VERSION 5.8 ;
BUSBITCHARS "[]" ;
DIVIDERCHAR "/" ;
UNITS
    DATABASE MICRONS 1000 ;
END UNITS

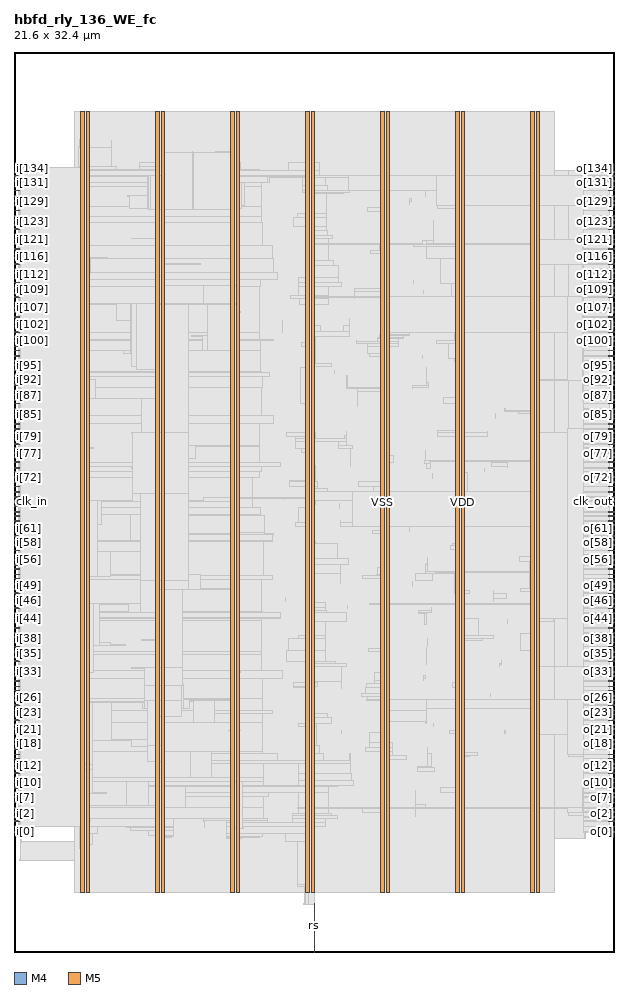
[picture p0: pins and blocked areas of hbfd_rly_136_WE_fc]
MACRO hbfd_rly_136_WE_fc
  FOREIGN hbfd_rly_136_WE_fc 0 0 ;
  CLASS BLOCK ;
  SIZE 21.6 BY 32.4 ;
  PIN clk_in
    DIRECTION INPUT ;
    USE SIGNAL ;
    PORT
      LAYER M4 ;
        RECT  0 16.224 0.192 16.248 ;
    END
  END clk_in
  PIN clk_out
    DIRECTION OUTPUT ;
    USE SIGNAL ;
    PORT
      LAYER M4 ;
        RECT  21.408 16.224 21.6 16.248 ;
    END
  END clk_out
  PIN i[0]
    DIRECTION INPUT ;
    USE SIGNAL ;
    PORT
      LAYER M4 ;
        RECT  0 4.32 0.192 4.344 ;
    END
  END i[0]
  PIN i[100]
    DIRECTION INPUT ;
    USE SIGNAL ;
    PORT
      LAYER M4 ;
        RECT  0 21.984 0.192 22.008 ;
    END
  END i[100]
  PIN i[101]
    DIRECTION INPUT ;
    USE SIGNAL ;
    PORT
      LAYER M4 ;
        RECT  0 22.128 0.192 22.152 ;
    END
  END i[101]
  PIN i[102]
    DIRECTION INPUT ;
    USE SIGNAL ;
    PORT
      LAYER M4 ;
        RECT  0 22.32 0.192 22.344 ;
    END
  END i[102]
  PIN i[103]
    DIRECTION INPUT ;
    USE SIGNAL ;
    PORT
      LAYER M4 ;
        RECT  0 22.512 0.192 22.536 ;
    END
  END i[103]
  PIN i[104]
    DIRECTION INPUT ;
    USE SIGNAL ;
    PORT
      LAYER M4 ;
        RECT  0 22.656 0.192 22.68 ;
    END
  END i[104]
  PIN i[105]
    DIRECTION INPUT ;
    USE SIGNAL ;
    PORT
      LAYER M4 ;
        RECT  0 22.848 0.192 22.872 ;
    END
  END i[105]
  PIN i[106]
    DIRECTION INPUT ;
    USE SIGNAL ;
    PORT
      LAYER M4 ;
        RECT  0 23.04 0.192 23.064 ;
    END
  END i[106]
  PIN i[107]
    DIRECTION INPUT ;
    USE SIGNAL ;
    PORT
      LAYER M4 ;
        RECT  0 23.184 0.192 23.208 ;
    END
  END i[107]
  PIN i[108]
    DIRECTION INPUT ;
    USE SIGNAL ;
    PORT
      LAYER M4 ;
        RECT  0 23.376 0.192 23.4 ;
    END
  END i[108]
  PIN i[109]
    DIRECTION INPUT ;
    USE SIGNAL ;
    PORT
      LAYER M4 ;
        RECT  0 23.568 0.192 23.592 ;
    END
  END i[109]
  PIN i[10]
    DIRECTION INPUT ;
    USE SIGNAL ;
    PORT
      LAYER M4 ;
        RECT  0 6.096 0.192 6.12 ;
    END
  END i[10]
  PIN i[110]
    DIRECTION INPUT ;
    USE SIGNAL ;
    PORT
      LAYER M4 ;
        RECT  0 23.712 0.192 23.736 ;
    END
  END i[110]
  PIN i[111]
    DIRECTION INPUT ;
    USE SIGNAL ;
    PORT
      LAYER M4 ;
        RECT  0 23.904 0.192 23.928 ;
    END
  END i[111]
  PIN i[112]
    DIRECTION INPUT ;
    USE SIGNAL ;
    PORT
      LAYER M4 ;
        RECT  0 24.096 0.192 24.12 ;
    END
  END i[112]
  PIN i[113]
    DIRECTION INPUT ;
    USE SIGNAL ;
    PORT
      LAYER M4 ;
        RECT  0 24.24 0.192 24.264 ;
    END
  END i[113]
  PIN i[114]
    DIRECTION INPUT ;
    USE SIGNAL ;
    PORT
      LAYER M4 ;
        RECT  0 24.432 0.192 24.456 ;
    END
  END i[114]
  PIN i[115]
    DIRECTION INPUT ;
    USE SIGNAL ;
    PORT
      LAYER M4 ;
        RECT  0 24.576 0.192 24.6 ;
    END
  END i[115]
  PIN i[116]
    DIRECTION INPUT ;
    USE SIGNAL ;
    PORT
      LAYER M4 ;
        RECT  0 24.768 0.192 24.792 ;
    END
  END i[116]
  PIN i[117]
    DIRECTION INPUT ;
    USE SIGNAL ;
    PORT
      LAYER M4 ;
        RECT  0 24.96 0.192 24.984 ;
    END
  END i[117]
  PIN i[118]
    DIRECTION INPUT ;
    USE SIGNAL ;
    PORT
      LAYER M4 ;
        RECT  0 25.104 0.192 25.128 ;
    END
  END i[118]
  PIN i[119]
    DIRECTION INPUT ;
    USE SIGNAL ;
    PORT
      LAYER M4 ;
        RECT  0 25.296 0.192 25.32 ;
    END
  END i[119]
  PIN i[11]
    DIRECTION INPUT ;
    USE SIGNAL ;
    PORT
      LAYER M4 ;
        RECT  0 6.24 0.192 6.264 ;
    END
  END i[11]
  PIN i[120]
    DIRECTION INPUT ;
    USE SIGNAL ;
    PORT
      LAYER M4 ;
        RECT  0 25.488 0.192 25.512 ;
    END
  END i[120]
  PIN i[121]
    DIRECTION INPUT ;
    USE SIGNAL ;
    PORT
      LAYER M4 ;
        RECT  0 25.632 0.192 25.656 ;
    END
  END i[121]
  PIN i[122]
    DIRECTION INPUT ;
    USE SIGNAL ;
    PORT
      LAYER M4 ;
        RECT  0 25.824 0.192 25.848 ;
    END
  END i[122]
  PIN i[123]
    DIRECTION INPUT ;
    USE SIGNAL ;
    PORT
      LAYER M4 ;
        RECT  0 26.016 0.192 26.04 ;
    END
  END i[123]
  PIN i[124]
    DIRECTION INPUT ;
    USE SIGNAL ;
    PORT
      LAYER M4 ;
        RECT  0 26.16 0.192 26.184 ;
    END
  END i[124]
  PIN i[125]
    DIRECTION INPUT ;
    USE SIGNAL ;
    PORT
      LAYER M4 ;
        RECT  0 26.352 0.192 26.376 ;
    END
  END i[125]
  PIN i[126]
    DIRECTION INPUT ;
    USE SIGNAL ;
    PORT
      LAYER M4 ;
        RECT  0 26.496 0.192 26.52 ;
    END
  END i[126]
  PIN i[127]
    DIRECTION INPUT ;
    USE SIGNAL ;
    PORT
      LAYER M4 ;
        RECT  0 26.688 0.192 26.712 ;
    END
  END i[127]
  PIN i[128]
    DIRECTION INPUT ;
    USE SIGNAL ;
    PORT
      LAYER M4 ;
        RECT  0 26.88 0.192 26.904 ;
    END
  END i[128]
  PIN i[129]
    DIRECTION INPUT ;
    USE SIGNAL ;
    PORT
      LAYER M4 ;
        RECT  0 27.024 0.192 27.048 ;
    END
  END i[129]
  PIN i[12]
    DIRECTION INPUT ;
    USE SIGNAL ;
    PORT
      LAYER M4 ;
        RECT  0 6.432 0.192 6.456 ;
    END
  END i[12]
  PIN i[130]
    DIRECTION INPUT ;
    USE SIGNAL ;
    PORT
      LAYER M4 ;
        RECT  0 27.216 0.192 27.24 ;
    END
  END i[130]
  PIN i[131]
    DIRECTION INPUT ;
    USE SIGNAL ;
    PORT
      LAYER M4 ;
        RECT  0 27.408 0.192 27.432 ;
    END
  END i[131]
  PIN i[132]
    DIRECTION INPUT ;
    USE SIGNAL ;
    PORT
      LAYER M4 ;
        RECT  0 27.552 0.192 27.576 ;
    END
  END i[132]
  PIN i[133]
    DIRECTION INPUT ;
    USE SIGNAL ;
    PORT
      LAYER M4 ;
        RECT  0 27.744 0.192 27.768 ;
    END
  END i[133]
  PIN i[134]
    DIRECTION INPUT ;
    USE SIGNAL ;
    PORT
      LAYER M4 ;
        RECT  0 27.936 0.192 27.96 ;
    END
  END i[134]
  PIN i[135]
    DIRECTION INPUT ;
    USE SIGNAL ;
    PORT
      LAYER M4 ;
        RECT  0 28.08 0.192 28.104 ;
    END
  END i[135]
  PIN i[13]
    DIRECTION INPUT ;
    USE SIGNAL ;
    PORT
      LAYER M4 ;
        RECT  0 6.624 0.192 6.648 ;
    END
  END i[13]
  PIN i[14]
    DIRECTION INPUT ;
    USE SIGNAL ;
    PORT
      LAYER M4 ;
        RECT  0 6.768 0.192 6.792 ;
    END
  END i[14]
  PIN i[15]
    DIRECTION INPUT ;
    USE SIGNAL ;
    PORT
      LAYER M4 ;
        RECT  0 6.96 0.192 6.984 ;
    END
  END i[15]
  PIN i[16]
    DIRECTION INPUT ;
    USE SIGNAL ;
    PORT
      LAYER M4 ;
        RECT  0 7.104 0.192 7.128 ;
    END
  END i[16]
  PIN i[17]
    DIRECTION INPUT ;
    USE SIGNAL ;
    PORT
      LAYER M4 ;
        RECT  0 7.296 0.192 7.32 ;
    END
  END i[17]
  PIN i[18]
    DIRECTION INPUT ;
    USE SIGNAL ;
    PORT
      LAYER M4 ;
        RECT  0 7.488 0.192 7.512 ;
    END
  END i[18]
  PIN i[19]
    DIRECTION INPUT ;
    USE SIGNAL ;
    PORT
      LAYER M4 ;
        RECT  0 7.632 0.192 7.656 ;
    END
  END i[19]
  PIN i[1]
    DIRECTION INPUT ;
    USE SIGNAL ;
    PORT
      LAYER M4 ;
        RECT  0 4.512 0.192 4.536 ;
    END
  END i[1]
  PIN i[20]
    DIRECTION INPUT ;
    USE SIGNAL ;
    PORT
      LAYER M4 ;
        RECT  0 7.824 0.192 7.848 ;
    END
  END i[20]
  PIN i[21]
    DIRECTION INPUT ;
    USE SIGNAL ;
    PORT
      LAYER M4 ;
        RECT  0 8.016 0.192 8.04 ;
    END
  END i[21]
  PIN i[22]
    DIRECTION INPUT ;
    USE SIGNAL ;
    PORT
      LAYER M4 ;
        RECT  0 8.16 0.192 8.184 ;
    END
  END i[22]
  PIN i[23]
    DIRECTION INPUT ;
    USE SIGNAL ;
    PORT
      LAYER M4 ;
        RECT  0 8.352 0.192 8.376 ;
    END
  END i[23]
  PIN i[24]
    DIRECTION INPUT ;
    USE SIGNAL ;
    PORT
      LAYER M4 ;
        RECT  0 8.544 0.192 8.568 ;
    END
  END i[24]
  PIN i[25]
    DIRECTION INPUT ;
    USE SIGNAL ;
    PORT
      LAYER M4 ;
        RECT  0 8.688 0.192 8.712 ;
    END
  END i[25]
  PIN i[26]
    DIRECTION INPUT ;
    USE SIGNAL ;
    PORT
      LAYER M4 ;
        RECT  0 8.88 0.192 8.904 ;
    END
  END i[26]
  PIN i[27]
    DIRECTION INPUT ;
    USE SIGNAL ;
    PORT
      LAYER M4 ;
        RECT  0 9.072 0.192 9.096 ;
    END
  END i[27]
  PIN i[28]
    DIRECTION INPUT ;
    USE SIGNAL ;
    PORT
      LAYER M4 ;
        RECT  0 9.216 0.192 9.24 ;
    END
  END i[28]
  PIN i[29]
    DIRECTION INPUT ;
    USE SIGNAL ;
    PORT
      LAYER M4 ;
        RECT  0 9.408 0.192 9.432 ;
    END
  END i[29]
  PIN i[2]
    DIRECTION INPUT ;
    USE SIGNAL ;
    PORT
      LAYER M4 ;
        RECT  0 4.704 0.192 4.728 ;
    END
  END i[2]
  PIN i[30]
    DIRECTION INPUT ;
    USE SIGNAL ;
    PORT
      LAYER M4 ;
        RECT  0 9.552 0.192 9.576 ;
    END
  END i[30]
  PIN i[31]
    DIRECTION INPUT ;
    USE SIGNAL ;
    PORT
      LAYER M4 ;
        RECT  0 9.744 0.192 9.768 ;
    END
  END i[31]
  PIN i[32]
    DIRECTION INPUT ;
    USE SIGNAL ;
    PORT
      LAYER M4 ;
        RECT  0 9.936 0.192 9.96 ;
    END
  END i[32]
  PIN i[33]
    DIRECTION INPUT ;
    USE SIGNAL ;
    PORT
      LAYER M4 ;
        RECT  0 10.08 0.192 10.104 ;
    END
  END i[33]
  PIN i[34]
    DIRECTION INPUT ;
    USE SIGNAL ;
    PORT
      LAYER M4 ;
        RECT  0 10.272 0.192 10.296 ;
    END
  END i[34]
  PIN i[35]
    DIRECTION INPUT ;
    USE SIGNAL ;
    PORT
      LAYER M4 ;
        RECT  0 10.464 0.192 10.488 ;
    END
  END i[35]
  PIN i[36]
    DIRECTION INPUT ;
    USE SIGNAL ;
    PORT
      LAYER M4 ;
        RECT  0 10.608 0.192 10.632 ;
    END
  END i[36]
  PIN i[37]
    DIRECTION INPUT ;
    USE SIGNAL ;
    PORT
      LAYER M4 ;
        RECT  0 10.8 0.192 10.824 ;
    END
  END i[37]
  PIN i[38]
    DIRECTION INPUT ;
    USE SIGNAL ;
    PORT
      LAYER M4 ;
        RECT  0 10.992 0.192 11.016 ;
    END
  END i[38]
  PIN i[39]
    DIRECTION INPUT ;
    USE SIGNAL ;
    PORT
      LAYER M4 ;
        RECT  0 11.136 0.192 11.16 ;
    END
  END i[39]
  PIN i[3]
    DIRECTION INPUT ;
    USE SIGNAL ;
    PORT
      LAYER M4 ;
        RECT  0 4.848 0.192 4.872 ;
    END
  END i[3]
  PIN i[40]
    DIRECTION INPUT ;
    USE SIGNAL ;
    PORT
      LAYER M4 ;
        RECT  0 11.328 0.192 11.352 ;
    END
  END i[40]
  PIN i[41]
    DIRECTION INPUT ;
    USE SIGNAL ;
    PORT
      LAYER M4 ;
        RECT  0 11.472 0.192 11.496 ;
    END
  END i[41]
  PIN i[42]
    DIRECTION INPUT ;
    USE SIGNAL ;
    PORT
      LAYER M4 ;
        RECT  0 11.664 0.192 11.688 ;
    END
  END i[42]
  PIN i[43]
    DIRECTION INPUT ;
    USE SIGNAL ;
    PORT
      LAYER M4 ;
        RECT  0 11.856 0.192 11.88 ;
    END
  END i[43]
  PIN i[44]
    DIRECTION INPUT ;
    USE SIGNAL ;
    PORT
      LAYER M4 ;
        RECT  0 12 0.192 12.024 ;
    END
  END i[44]
  PIN i[45]
    DIRECTION INPUT ;
    USE SIGNAL ;
    PORT
      LAYER M4 ;
        RECT  0 12.192 0.192 12.216 ;
    END
  END i[45]
  PIN i[46]
    DIRECTION INPUT ;
    USE SIGNAL ;
    PORT
      LAYER M4 ;
        RECT  0 12.384 0.192 12.408 ;
    END
  END i[46]
  PIN i[47]
    DIRECTION INPUT ;
    USE SIGNAL ;
    PORT
      LAYER M4 ;
        RECT  0 12.528 0.192 12.552 ;
    END
  END i[47]
  PIN i[48]
    DIRECTION INPUT ;
    USE SIGNAL ;
    PORT
      LAYER M4 ;
        RECT  0 12.72 0.192 12.744 ;
    END
  END i[48]
  PIN i[49]
    DIRECTION INPUT ;
    USE SIGNAL ;
    PORT
      LAYER M4 ;
        RECT  0 12.912 0.192 12.936 ;
    END
  END i[49]
  PIN i[4]
    DIRECTION INPUT ;
    USE SIGNAL ;
    PORT
      LAYER M4 ;
        RECT  0 5.04 0.192 5.064 ;
    END
  END i[4]
  PIN i[50]
    DIRECTION INPUT ;
    USE SIGNAL ;
    PORT
      LAYER M4 ;
        RECT  0 13.056 0.192 13.08 ;
    END
  END i[50]
  PIN i[51]
    DIRECTION INPUT ;
    USE SIGNAL ;
    PORT
      LAYER M4 ;
        RECT  0 13.248 0.192 13.272 ;
    END
  END i[51]
  PIN i[52]
    DIRECTION INPUT ;
    USE SIGNAL ;
    PORT
      LAYER M4 ;
        RECT  0 13.44 0.192 13.464 ;
    END
  END i[52]
  PIN i[53]
    DIRECTION INPUT ;
    USE SIGNAL ;
    PORT
      LAYER M4 ;
        RECT  0 13.584 0.192 13.608 ;
    END
  END i[53]
  PIN i[54]
    DIRECTION INPUT ;
    USE SIGNAL ;
    PORT
      LAYER M4 ;
        RECT  0 13.776 0.192 13.8 ;
    END
  END i[54]
  PIN i[55]
    DIRECTION INPUT ;
    USE SIGNAL ;
    PORT
      LAYER M4 ;
        RECT  0 13.92 0.192 13.944 ;
    END
  END i[55]
  PIN i[56]
    DIRECTION INPUT ;
    USE SIGNAL ;
    PORT
      LAYER M4 ;
        RECT  0 14.112 0.192 14.136 ;
    END
  END i[56]
  PIN i[57]
    DIRECTION INPUT ;
    USE SIGNAL ;
    PORT
      LAYER M4 ;
        RECT  0 14.304 0.192 14.328 ;
    END
  END i[57]
  PIN i[58]
    DIRECTION INPUT ;
    USE SIGNAL ;
    PORT
      LAYER M4 ;
        RECT  0 14.448 0.192 14.472 ;
    END
  END i[58]
  PIN i[59]
    DIRECTION INPUT ;
    USE SIGNAL ;
    PORT
      LAYER M4 ;
        RECT  0 14.64 0.192 14.664 ;
    END
  END i[59]
  PIN i[5]
    DIRECTION INPUT ;
    USE SIGNAL ;
    PORT
      LAYER M4 ;
        RECT  0 5.184 0.192 5.208 ;
    END
  END i[5]
  PIN i[60]
    DIRECTION INPUT ;
    USE SIGNAL ;
    PORT
      LAYER M4 ;
        RECT  0 14.832 0.192 14.856 ;
    END
  END i[60]
  PIN i[61]
    DIRECTION INPUT ;
    USE SIGNAL ;
    PORT
      LAYER M4 ;
        RECT  0 14.976 0.192 15 ;
    END
  END i[61]
  PIN i[62]
    DIRECTION INPUT ;
    USE SIGNAL ;
    PORT
      LAYER M4 ;
        RECT  0 15.168 0.192 15.192 ;
    END
  END i[62]
  PIN i[63]
    DIRECTION INPUT ;
    USE SIGNAL ;
    PORT
      LAYER M4 ;
        RECT  0 15.36 0.192 15.384 ;
    END
  END i[63]
  PIN i[64]
    DIRECTION INPUT ;
    USE SIGNAL ;
    PORT
      LAYER M4 ;
        RECT  0 15.504 0.192 15.528 ;
    END
  END i[64]
  PIN i[65]
    DIRECTION INPUT ;
    USE SIGNAL ;
    PORT
      LAYER M4 ;
        RECT  0 15.696 0.192 15.72 ;
    END
  END i[65]
  PIN i[66]
    DIRECTION INPUT ;
    USE SIGNAL ;
    PORT
      LAYER M4 ;
        RECT  0 15.84 0.192 15.864 ;
    END
  END i[66]
  PIN i[67]
    DIRECTION INPUT ;
    USE SIGNAL ;
    PORT
      LAYER M4 ;
        RECT  0 16.032 0.192 16.056 ;
    END
  END i[67]
  PIN i[68]
    DIRECTION INPUT ;
    USE SIGNAL ;
    PORT
      LAYER M4 ;
        RECT  0 16.368 0.192 16.392 ;
    END
  END i[68]
  PIN i[69]
    DIRECTION INPUT ;
    USE SIGNAL ;
    PORT
      LAYER M4 ;
        RECT  0 16.56 0.192 16.584 ;
    END
  END i[69]
  PIN i[6]
    DIRECTION INPUT ;
    USE SIGNAL ;
    PORT
      LAYER M4 ;
        RECT  0 5.376 0.192 5.4 ;
    END
  END i[6]
  PIN i[70]
    DIRECTION INPUT ;
    USE SIGNAL ;
    PORT
      LAYER M4 ;
        RECT  0 16.752 0.192 16.776 ;
    END
  END i[70]
  PIN i[71]
    DIRECTION INPUT ;
    USE SIGNAL ;
    PORT
      LAYER M4 ;
        RECT  0 16.896 0.192 16.92 ;
    END
  END i[71]
  PIN i[72]
    DIRECTION INPUT ;
    USE SIGNAL ;
    PORT
      LAYER M4 ;
        RECT  0 17.088 0.192 17.112 ;
    END
  END i[72]
  PIN i[73]
    DIRECTION INPUT ;
    USE SIGNAL ;
    PORT
      LAYER M4 ;
        RECT  0 17.28 0.192 17.304 ;
    END
  END i[73]
  PIN i[74]
    DIRECTION INPUT ;
    USE SIGNAL ;
    PORT
      LAYER M4 ;
        RECT  0 17.424 0.192 17.448 ;
    END
  END i[74]
  PIN i[75]
    DIRECTION INPUT ;
    USE SIGNAL ;
    PORT
      LAYER M4 ;
        RECT  0 17.616 0.192 17.64 ;
    END
  END i[75]
  PIN i[76]
    DIRECTION INPUT ;
    USE SIGNAL ;
    PORT
      LAYER M4 ;
        RECT  0 17.808 0.192 17.832 ;
    END
  END i[76]
  PIN i[77]
    DIRECTION INPUT ;
    USE SIGNAL ;
    PORT
      LAYER M4 ;
        RECT  0 17.952 0.192 17.976 ;
    END
  END i[77]
  PIN i[78]
    DIRECTION INPUT ;
    USE SIGNAL ;
    PORT
      LAYER M4 ;
        RECT  0 18.144 0.192 18.168 ;
    END
  END i[78]
  PIN i[79]
    DIRECTION INPUT ;
    USE SIGNAL ;
    PORT
      LAYER M4 ;
        RECT  0 18.288 0.192 18.312 ;
    END
  END i[79]
  PIN i[7]
    DIRECTION INPUT ;
    USE SIGNAL ;
    PORT
      LAYER M4 ;
        RECT  0 5.568 0.192 5.592 ;
    END
  END i[7]
  PIN i[80]
    DIRECTION INPUT ;
    USE SIGNAL ;
    PORT
      LAYER M4 ;
        RECT  0 18.48 0.192 18.504 ;
    END
  END i[80]
  PIN i[81]
    DIRECTION INPUT ;
    USE SIGNAL ;
    PORT
      LAYER M4 ;
        RECT  0 18.672 0.192 18.696 ;
    END
  END i[81]
  PIN i[82]
    DIRECTION INPUT ;
    USE SIGNAL ;
    PORT
      LAYER M4 ;
        RECT  0 18.816 0.192 18.84 ;
    END
  END i[82]
  PIN i[83]
    DIRECTION INPUT ;
    USE SIGNAL ;
    PORT
      LAYER M4 ;
        RECT  0 19.008 0.192 19.032 ;
    END
  END i[83]
  PIN i[84]
    DIRECTION INPUT ;
    USE SIGNAL ;
    PORT
      LAYER M4 ;
        RECT  0 19.2 0.192 19.224 ;
    END
  END i[84]
  PIN i[85]
    DIRECTION INPUT ;
    USE SIGNAL ;
    PORT
      LAYER M4 ;
        RECT  0 19.344 0.192 19.368 ;
    END
  END i[85]
  PIN i[86]
    DIRECTION INPUT ;
    USE SIGNAL ;
    PORT
      LAYER M4 ;
        RECT  0 19.536 0.192 19.56 ;
    END
  END i[86]
  PIN i[87]
    DIRECTION INPUT ;
    USE SIGNAL ;
    PORT
      LAYER M4 ;
        RECT  0 19.728 0.192 19.752 ;
    END
  END i[87]
  PIN i[88]
    DIRECTION INPUT ;
    USE SIGNAL ;
    PORT
      LAYER M4 ;
        RECT  0 19.872 0.192 19.896 ;
    END
  END i[88]
  PIN i[89]
    DIRECTION INPUT ;
    USE SIGNAL ;
    PORT
      LAYER M4 ;
        RECT  0 20.064 0.192 20.088 ;
    END
  END i[89]
  PIN i[8]
    DIRECTION INPUT ;
    USE SIGNAL ;
    PORT
      LAYER M4 ;
        RECT  0 5.712 0.192 5.736 ;
    END
  END i[8]
  PIN i[90]
    DIRECTION INPUT ;
    USE SIGNAL ;
    PORT
      LAYER M4 ;
        RECT  0 20.208 0.192 20.232 ;
    END
  END i[90]
  PIN i[91]
    DIRECTION INPUT ;
    USE SIGNAL ;
    PORT
      LAYER M4 ;
        RECT  0 20.4 0.192 20.424 ;
    END
  END i[91]
  PIN i[92]
    DIRECTION INPUT ;
    USE SIGNAL ;
    PORT
      LAYER M4 ;
        RECT  0 20.592 0.192 20.616 ;
    END
  END i[92]
  PIN i[93]
    DIRECTION INPUT ;
    USE SIGNAL ;
    PORT
      LAYER M4 ;
        RECT  0 20.736 0.192 20.76 ;
    END
  END i[93]
  PIN i[94]
    DIRECTION INPUT ;
    USE SIGNAL ;
    PORT
      LAYER M4 ;
        RECT  0 20.928 0.192 20.952 ;
    END
  END i[94]
  PIN i[95]
    DIRECTION INPUT ;
    USE SIGNAL ;
    PORT
      LAYER M4 ;
        RECT  0 21.12 0.192 21.144 ;
    END
  END i[95]
  PIN i[96]
    DIRECTION INPUT ;
    USE SIGNAL ;
    PORT
      LAYER M4 ;
        RECT  0 21.264 0.192 21.288 ;
    END
  END i[96]
  PIN i[97]
    DIRECTION INPUT ;
    USE SIGNAL ;
    PORT
      LAYER M4 ;
        RECT  0 21.456 0.192 21.48 ;
    END
  END i[97]
  PIN i[98]
    DIRECTION INPUT ;
    USE SIGNAL ;
    PORT
      LAYER M4 ;
        RECT  0 21.648 0.192 21.672 ;
    END
  END i[98]
  PIN i[99]
    DIRECTION INPUT ;
    USE SIGNAL ;
    PORT
      LAYER M4 ;
        RECT  0 21.792 0.192 21.816 ;
    END
  END i[99]
  PIN i[9]
    DIRECTION INPUT ;
    USE SIGNAL ;
    PORT
      LAYER M4 ;
        RECT  0 5.904 0.192 5.928 ;
    END
  END i[9]
  PIN o[0]
    DIRECTION OUTPUT ;
    USE SIGNAL ;
    PORT
      LAYER M4 ;
        RECT  21.408 4.32 21.6 4.344 ;
    END
  END o[0]
  PIN o[100]
    DIRECTION OUTPUT ;
    USE SIGNAL ;
    PORT
      LAYER M4 ;
        RECT  21.408 21.984 21.6 22.008 ;
    END
  END o[100]
  PIN o[101]
    DIRECTION OUTPUT ;
    USE SIGNAL ;
    PORT
      LAYER M4 ;
        RECT  21.408 22.128 21.6 22.152 ;
    END
  END o[101]
  PIN o[102]
    DIRECTION OUTPUT ;
    USE SIGNAL ;
    PORT
      LAYER M4 ;
        RECT  21.408 22.32 21.6 22.344 ;
    END
  END o[102]
  PIN o[103]
    DIRECTION OUTPUT ;
    USE SIGNAL ;
    PORT
      LAYER M4 ;
        RECT  21.408 22.512 21.6 22.536 ;
    END
  END o[103]
  PIN o[104]
    DIRECTION OUTPUT ;
    USE SIGNAL ;
    PORT
      LAYER M4 ;
        RECT  21.408 22.656 21.6 22.68 ;
    END
  END o[104]
  PIN o[105]
    DIRECTION OUTPUT ;
    USE SIGNAL ;
    PORT
      LAYER M4 ;
        RECT  21.408 22.848 21.6 22.872 ;
    END
  END o[105]
  PIN o[106]
    DIRECTION OUTPUT ;
    USE SIGNAL ;
    PORT
      LAYER M4 ;
        RECT  21.408 23.04 21.6 23.064 ;
    END
  END o[106]
  PIN o[107]
    DIRECTION OUTPUT ;
    USE SIGNAL ;
    PORT
      LAYER M4 ;
        RECT  21.408 23.184 21.6 23.208 ;
    END
  END o[107]
  PIN o[108]
    DIRECTION OUTPUT ;
    USE SIGNAL ;
    PORT
      LAYER M4 ;
        RECT  21.408 23.376 21.6 23.4 ;
    END
  END o[108]
  PIN o[109]
    DIRECTION OUTPUT ;
    USE SIGNAL ;
    PORT
      LAYER M4 ;
        RECT  21.408 23.568 21.6 23.592 ;
    END
  END o[109]
  PIN o[10]
    DIRECTION OUTPUT ;
    USE SIGNAL ;
    PORT
      LAYER M4 ;
        RECT  21.408 6.096 21.6 6.12 ;
    END
  END o[10]
  PIN o[110]
    DIRECTION OUTPUT ;
    USE SIGNAL ;
    PORT
      LAYER M4 ;
        RECT  21.408 23.712 21.6 23.736 ;
    END
  END o[110]
  PIN o[111]
    DIRECTION OUTPUT ;
    USE SIGNAL ;
    PORT
      LAYER M4 ;
        RECT  21.408 23.904 21.6 23.928 ;
    END
  END o[111]
  PIN o[112]
    DIRECTION OUTPUT ;
    USE SIGNAL ;
    PORT
      LAYER M4 ;
        RECT  21.408 24.096 21.6 24.12 ;
    END
  END o[112]
  PIN o[113]
    DIRECTION OUTPUT ;
    USE SIGNAL ;
    PORT
      LAYER M4 ;
        RECT  21.408 24.24 21.6 24.264 ;
    END
  END o[113]
  PIN o[114]
    DIRECTION OUTPUT ;
    USE SIGNAL ;
    PORT
      LAYER M4 ;
        RECT  21.408 24.432 21.6 24.456 ;
    END
  END o[114]
  PIN o[115]
    DIRECTION OUTPUT ;
    USE SIGNAL ;
    PORT
      LAYER M4 ;
        RECT  21.408 24.576 21.6 24.6 ;
    END
  END o[115]
  PIN o[116]
    DIRECTION OUTPUT ;
    USE SIGNAL ;
    PORT
      LAYER M4 ;
        RECT  21.408 24.768 21.6 24.792 ;
    END
  END o[116]
  PIN o[117]
    DIRECTION OUTPUT ;
    USE SIGNAL ;
    PORT
      LAYER M4 ;
        RECT  21.408 24.96 21.6 24.984 ;
    END
  END o[117]
  PIN o[118]
    DIRECTION OUTPUT ;
    USE SIGNAL ;
    PORT
      LAYER M4 ;
        RECT  21.408 25.104 21.6 25.128 ;
    END
  END o[118]
  PIN o[119]
    DIRECTION OUTPUT ;
    USE SIGNAL ;
    PORT
      LAYER M4 ;
        RECT  21.408 25.296 21.6 25.32 ;
    END
  END o[119]
  PIN o[11]
    DIRECTION OUTPUT ;
    USE SIGNAL ;
    PORT
      LAYER M4 ;
        RECT  21.408 6.24 21.6 6.264 ;
    END
  END o[11]
  PIN o[120]
    DIRECTION OUTPUT ;
    USE SIGNAL ;
    PORT
      LAYER M4 ;
        RECT  21.408 25.488 21.6 25.512 ;
    END
  END o[120]
  PIN o[121]
    DIRECTION OUTPUT ;
    USE SIGNAL ;
    PORT
      LAYER M4 ;
        RECT  21.408 25.632 21.6 25.656 ;
    END
  END o[121]
  PIN o[122]
    DIRECTION OUTPUT ;
    USE SIGNAL ;
    PORT
      LAYER M4 ;
        RECT  21.408 25.824 21.6 25.848 ;
    END
  END o[122]
  PIN o[123]
    DIRECTION OUTPUT ;
    USE SIGNAL ;
    PORT
      LAYER M4 ;
        RECT  21.408 26.016 21.6 26.04 ;
    END
  END o[123]
  PIN o[124]
    DIRECTION OUTPUT ;
    USE SIGNAL ;
    PORT
      LAYER M4 ;
        RECT  21.408 26.16 21.6 26.184 ;
    END
  END o[124]
  PIN o[125]
    DIRECTION OUTPUT ;
    USE SIGNAL ;
    PORT
      LAYER M4 ;
        RECT  21.408 26.352 21.6 26.376 ;
    END
  END o[125]
  PIN o[126]
    DIRECTION OUTPUT ;
    USE SIGNAL ;
    PORT
      LAYER M4 ;
        RECT  21.408 26.496 21.6 26.52 ;
    END
  END o[126]
  PIN o[127]
    DIRECTION OUTPUT ;
    USE SIGNAL ;
    PORT
      LAYER M4 ;
        RECT  21.408 26.688 21.6 26.712 ;
    END
  END o[127]
  PIN o[128]
    DIRECTION OUTPUT ;
    USE SIGNAL ;
    PORT
      LAYER M4 ;
        RECT  21.408 26.88 21.6 26.904 ;
    END
  END o[128]
  PIN o[129]
    DIRECTION OUTPUT ;
    USE SIGNAL ;
    PORT
      LAYER M4 ;
        RECT  21.408 27.024 21.6 27.048 ;
    END
  END o[129]
  PIN o[12]
    DIRECTION OUTPUT ;
    USE SIGNAL ;
    PORT
      LAYER M4 ;
        RECT  21.408 6.432 21.6 6.456 ;
    END
  END o[12]
  PIN o[130]
    DIRECTION OUTPUT ;
    USE SIGNAL ;
    PORT
      LAYER M4 ;
        RECT  21.408 27.216 21.6 27.24 ;
    END
  END o[130]
  PIN o[131]
    DIRECTION OUTPUT ;
    USE SIGNAL ;
    PORT
      LAYER M4 ;
        RECT  21.408 27.408 21.6 27.432 ;
    END
  END o[131]
  PIN o[132]
    DIRECTION OUTPUT ;
    USE SIGNAL ;
    PORT
      LAYER M4 ;
        RECT  21.408 27.552 21.6 27.576 ;
    END
  END o[132]
  PIN o[133]
    DIRECTION OUTPUT ;
    USE SIGNAL ;
    PORT
      LAYER M4 ;
        RECT  21.408 27.744 21.6 27.768 ;
    END
  END o[133]
  PIN o[134]
    DIRECTION OUTPUT ;
    USE SIGNAL ;
    PORT
      LAYER M4 ;
        RECT  21.408 27.936 21.6 27.96 ;
    END
  END o[134]
  PIN o[135]
    DIRECTION OUTPUT ;
    USE SIGNAL ;
    PORT
      LAYER M4 ;
        RECT  21.408 28.08 21.6 28.104 ;
    END
  END o[135]
  PIN o[13]
    DIRECTION OUTPUT ;
    USE SIGNAL ;
    PORT
      LAYER M4 ;
        RECT  21.408 6.624 21.6 6.648 ;
    END
  END o[13]
  PIN o[14]
    DIRECTION OUTPUT ;
    USE SIGNAL ;
    PORT
      LAYER M4 ;
        RECT  21.408 6.768 21.6 6.792 ;
    END
  END o[14]
  PIN o[15]
    DIRECTION OUTPUT ;
    USE SIGNAL ;
    PORT
      LAYER M4 ;
        RECT  21.408 6.96 21.6 6.984 ;
    END
  END o[15]
  PIN o[16]
    DIRECTION OUTPUT ;
    USE SIGNAL ;
    PORT
      LAYER M4 ;
        RECT  21.408 7.104 21.6 7.128 ;
    END
  END o[16]
  PIN o[17]
    DIRECTION OUTPUT ;
    USE SIGNAL ;
    PORT
      LAYER M4 ;
        RECT  21.408 7.296 21.6 7.32 ;
    END
  END o[17]
  PIN o[18]
    DIRECTION OUTPUT ;
    USE SIGNAL ;
    PORT
      LAYER M4 ;
        RECT  21.408 7.488 21.6 7.512 ;
    END
  END o[18]
  PIN o[19]
    DIRECTION OUTPUT ;
    USE SIGNAL ;
    PORT
      LAYER M4 ;
        RECT  21.408 7.632 21.6 7.656 ;
    END
  END o[19]
  PIN o[1]
    DIRECTION OUTPUT ;
    USE SIGNAL ;
    PORT
      LAYER M4 ;
        RECT  21.408 4.512 21.6 4.536 ;
    END
  END o[1]
  PIN o[20]
    DIRECTION OUTPUT ;
    USE SIGNAL ;
    PORT
      LAYER M4 ;
        RECT  21.408 7.824 21.6 7.848 ;
    END
  END o[20]
  PIN o[21]
    DIRECTION OUTPUT ;
    USE SIGNAL ;
    PORT
      LAYER M4 ;
        RECT  21.408 8.016 21.6 8.04 ;
    END
  END o[21]
  PIN o[22]
    DIRECTION OUTPUT ;
    USE SIGNAL ;
    PORT
      LAYER M4 ;
        RECT  21.408 8.16 21.6 8.184 ;
    END
  END o[22]
  PIN o[23]
    DIRECTION OUTPUT ;
    USE SIGNAL ;
    PORT
      LAYER M4 ;
        RECT  21.408 8.352 21.6 8.376 ;
    END
  END o[23]
  PIN o[24]
    DIRECTION OUTPUT ;
    USE SIGNAL ;
    PORT
      LAYER M4 ;
        RECT  21.408 8.544 21.6 8.568 ;
    END
  END o[24]
  PIN o[25]
    DIRECTION OUTPUT ;
    USE SIGNAL ;
    PORT
      LAYER M4 ;
        RECT  21.408 8.688 21.6 8.712 ;
    END
  END o[25]
  PIN o[26]
    DIRECTION OUTPUT ;
    USE SIGNAL ;
    PORT
      LAYER M4 ;
        RECT  21.408 8.88 21.6 8.904 ;
    END
  END o[26]
  PIN o[27]
    DIRECTION OUTPUT ;
    USE SIGNAL ;
    PORT
      LAYER M4 ;
        RECT  21.408 9.072 21.6 9.096 ;
    END
  END o[27]
  PIN o[28]
    DIRECTION OUTPUT ;
    USE SIGNAL ;
    PORT
      LAYER M4 ;
        RECT  21.408 9.216 21.6 9.24 ;
    END
  END o[28]
  PIN o[29]
    DIRECTION OUTPUT ;
    USE SIGNAL ;
    PORT
      LAYER M4 ;
        RECT  21.408 9.408 21.6 9.432 ;
    END
  END o[29]
  PIN o[2]
    DIRECTION OUTPUT ;
    USE SIGNAL ;
    PORT
      LAYER M4 ;
        RECT  21.408 4.704 21.6 4.728 ;
    END
  END o[2]
  PIN o[30]
    DIRECTION OUTPUT ;
    USE SIGNAL ;
    PORT
      LAYER M4 ;
        RECT  21.408 9.552 21.6 9.576 ;
    END
  END o[30]
  PIN o[31]
    DIRECTION OUTPUT ;
    USE SIGNAL ;
    PORT
      LAYER M4 ;
        RECT  21.408 9.744 21.6 9.768 ;
    END
  END o[31]
  PIN o[32]
    DIRECTION OUTPUT ;
    USE SIGNAL ;
    PORT
      LAYER M4 ;
        RECT  21.408 9.936 21.6 9.96 ;
    END
  END o[32]
  PIN o[33]
    DIRECTION OUTPUT ;
    USE SIGNAL ;
    PORT
      LAYER M4 ;
        RECT  21.408 10.08 21.6 10.104 ;
    END
  END o[33]
  PIN o[34]
    DIRECTION OUTPUT ;
    USE SIGNAL ;
    PORT
      LAYER M4 ;
        RECT  21.408 10.272 21.6 10.296 ;
    END
  END o[34]
  PIN o[35]
    DIRECTION OUTPUT ;
    USE SIGNAL ;
    PORT
      LAYER M4 ;
        RECT  21.408 10.464 21.6 10.488 ;
    END
  END o[35]
  PIN o[36]
    DIRECTION OUTPUT ;
    USE SIGNAL ;
    PORT
      LAYER M4 ;
        RECT  21.408 10.608 21.6 10.632 ;
    END
  END o[36]
  PIN o[37]
    DIRECTION OUTPUT ;
    USE SIGNAL ;
    PORT
      LAYER M4 ;
        RECT  21.408 10.8 21.6 10.824 ;
    END
  END o[37]
  PIN o[38]
    DIRECTION OUTPUT ;
    USE SIGNAL ;
    PORT
      LAYER M4 ;
        RECT  21.408 10.992 21.6 11.016 ;
    END
  END o[38]
  PIN o[39]
    DIRECTION OUTPUT ;
    USE SIGNAL ;
    PORT
      LAYER M4 ;
        RECT  21.408 11.136 21.6 11.16 ;
    END
  END o[39]
  PIN o[3]
    DIRECTION OUTPUT ;
    USE SIGNAL ;
    PORT
      LAYER M4 ;
        RECT  21.408 4.848 21.6 4.872 ;
    END
  END o[3]
  PIN o[40]
    DIRECTION OUTPUT ;
    USE SIGNAL ;
    PORT
      LAYER M4 ;
        RECT  21.408 11.328 21.6 11.352 ;
    END
  END o[40]
  PIN o[41]
    DIRECTION OUTPUT ;
    USE SIGNAL ;
    PORT
      LAYER M4 ;
        RECT  21.408 11.472 21.6 11.496 ;
    END
  END o[41]
  PIN o[42]
    DIRECTION OUTPUT ;
    USE SIGNAL ;
    PORT
      LAYER M4 ;
        RECT  21.408 11.664 21.6 11.688 ;
    END
  END o[42]
  PIN o[43]
    DIRECTION OUTPUT ;
    USE SIGNAL ;
    PORT
      LAYER M4 ;
        RECT  21.408 11.856 21.6 11.88 ;
    END
  END o[43]
  PIN o[44]
    DIRECTION OUTPUT ;
    USE SIGNAL ;
    PORT
      LAYER M4 ;
        RECT  21.408 12 21.6 12.024 ;
    END
  END o[44]
  PIN o[45]
    DIRECTION OUTPUT ;
    USE SIGNAL ;
    PORT
      LAYER M4 ;
        RECT  21.408 12.192 21.6 12.216 ;
    END
  END o[45]
  PIN o[46]
    DIRECTION OUTPUT ;
    USE SIGNAL ;
    PORT
      LAYER M4 ;
        RECT  21.408 12.384 21.6 12.408 ;
    END
  END o[46]
  PIN o[47]
    DIRECTION OUTPUT ;
    USE SIGNAL ;
    PORT
      LAYER M4 ;
        RECT  21.408 12.528 21.6 12.552 ;
    END
  END o[47]
  PIN o[48]
    DIRECTION OUTPUT ;
    USE SIGNAL ;
    PORT
      LAYER M4 ;
        RECT  21.408 12.72 21.6 12.744 ;
    END
  END o[48]
  PIN o[49]
    DIRECTION OUTPUT ;
    USE SIGNAL ;
    PORT
      LAYER M4 ;
        RECT  21.408 12.912 21.6 12.936 ;
    END
  END o[49]
  PIN o[4]
    DIRECTION OUTPUT ;
    USE SIGNAL ;
    PORT
      LAYER M4 ;
        RECT  21.408 5.04 21.6 5.064 ;
    END
  END o[4]
  PIN o[50]
    DIRECTION OUTPUT ;
    USE SIGNAL ;
    PORT
      LAYER M4 ;
        RECT  21.408 13.056 21.6 13.08 ;
    END
  END o[50]
  PIN o[51]
    DIRECTION OUTPUT ;
    USE SIGNAL ;
    PORT
      LAYER M4 ;
        RECT  21.408 13.248 21.6 13.272 ;
    END
  END o[51]
  PIN o[52]
    DIRECTION OUTPUT ;
    USE SIGNAL ;
    PORT
      LAYER M4 ;
        RECT  21.408 13.44 21.6 13.464 ;
    END
  END o[52]
  PIN o[53]
    DIRECTION OUTPUT ;
    USE SIGNAL ;
    PORT
      LAYER M4 ;
        RECT  21.408 13.584 21.6 13.608 ;
    END
  END o[53]
  PIN o[54]
    DIRECTION OUTPUT ;
    USE SIGNAL ;
    PORT
      LAYER M4 ;
        RECT  21.408 13.776 21.6 13.8 ;
    END
  END o[54]
  PIN o[55]
    DIRECTION OUTPUT ;
    USE SIGNAL ;
    PORT
      LAYER M4 ;
        RECT  21.408 13.92 21.6 13.944 ;
    END
  END o[55]
  PIN o[56]
    DIRECTION OUTPUT ;
    USE SIGNAL ;
    PORT
      LAYER M4 ;
        RECT  21.408 14.112 21.6 14.136 ;
    END
  END o[56]
  PIN o[57]
    DIRECTION OUTPUT ;
    USE SIGNAL ;
    PORT
      LAYER M4 ;
        RECT  21.408 14.304 21.6 14.328 ;
    END
  END o[57]
  PIN o[58]
    DIRECTION OUTPUT ;
    USE SIGNAL ;
    PORT
      LAYER M4 ;
        RECT  21.408 14.448 21.6 14.472 ;
    END
  END o[58]
  PIN o[59]
    DIRECTION OUTPUT ;
    USE SIGNAL ;
    PORT
      LAYER M4 ;
        RECT  21.408 14.64 21.6 14.664 ;
    END
  END o[59]
  PIN o[5]
    DIRECTION OUTPUT ;
    USE SIGNAL ;
    PORT
      LAYER M4 ;
        RECT  21.408 5.184 21.6 5.208 ;
    END
  END o[5]
  PIN o[60]
    DIRECTION OUTPUT ;
    USE SIGNAL ;
    PORT
      LAYER M4 ;
        RECT  21.408 14.832 21.6 14.856 ;
    END
  END o[60]
  PIN o[61]
    DIRECTION OUTPUT ;
    USE SIGNAL ;
    PORT
      LAYER M4 ;
        RECT  21.408 14.976 21.6 15 ;
    END
  END o[61]
  PIN o[62]
    DIRECTION OUTPUT ;
    USE SIGNAL ;
    PORT
      LAYER M4 ;
        RECT  21.408 15.168 21.6 15.192 ;
    END
  END o[62]
  PIN o[63]
    DIRECTION OUTPUT ;
    USE SIGNAL ;
    PORT
      LAYER M4 ;
        RECT  21.408 15.36 21.6 15.384 ;
    END
  END o[63]
  PIN o[64]
    DIRECTION OUTPUT ;
    USE SIGNAL ;
    PORT
      LAYER M4 ;
        RECT  21.408 15.504 21.6 15.528 ;
    END
  END o[64]
  PIN o[65]
    DIRECTION OUTPUT ;
    USE SIGNAL ;
    PORT
      LAYER M4 ;
        RECT  21.408 15.696 21.6 15.72 ;
    END
  END o[65]
  PIN o[66]
    DIRECTION OUTPUT ;
    USE SIGNAL ;
    PORT
      LAYER M4 ;
        RECT  21.408 15.84 21.6 15.864 ;
    END
  END o[66]
  PIN o[67]
    DIRECTION OUTPUT ;
    USE SIGNAL ;
    PORT
      LAYER M4 ;
        RECT  21.408 16.032 21.6 16.056 ;
    END
  END o[67]
  PIN o[68]
    DIRECTION OUTPUT ;
    USE SIGNAL ;
    PORT
      LAYER M4 ;
        RECT  21.408 16.368 21.6 16.392 ;
    END
  END o[68]
  PIN o[69]
    DIRECTION OUTPUT ;
    USE SIGNAL ;
    PORT
      LAYER M4 ;
        RECT  21.408 16.56 21.6 16.584 ;
    END
  END o[69]
  PIN o[6]
    DIRECTION OUTPUT ;
    USE SIGNAL ;
    PORT
      LAYER M4 ;
        RECT  21.408 5.376 21.6 5.4 ;
    END
  END o[6]
  PIN o[70]
    DIRECTION OUTPUT ;
    USE SIGNAL ;
    PORT
      LAYER M4 ;
        RECT  21.408 16.752 21.6 16.776 ;
    END
  END o[70]
  PIN o[71]
    DIRECTION OUTPUT ;
    USE SIGNAL ;
    PORT
      LAYER M4 ;
        RECT  21.408 16.896 21.6 16.92 ;
    END
  END o[71]
  PIN o[72]
    DIRECTION OUTPUT ;
    USE SIGNAL ;
    PORT
      LAYER M4 ;
        RECT  21.408 17.088 21.6 17.112 ;
    END
  END o[72]
  PIN o[73]
    DIRECTION OUTPUT ;
    USE SIGNAL ;
    PORT
      LAYER M4 ;
        RECT  21.408 17.28 21.6 17.304 ;
    END
  END o[73]
  PIN o[74]
    DIRECTION OUTPUT ;
    USE SIGNAL ;
    PORT
      LAYER M4 ;
        RECT  21.408 17.424 21.6 17.448 ;
    END
  END o[74]
  PIN o[75]
    DIRECTION OUTPUT ;
    USE SIGNAL ;
    PORT
      LAYER M4 ;
        RECT  21.408 17.616 21.6 17.64 ;
    END
  END o[75]
  PIN o[76]
    DIRECTION OUTPUT ;
    USE SIGNAL ;
    PORT
      LAYER M4 ;
        RECT  21.408 17.808 21.6 17.832 ;
    END
  END o[76]
  PIN o[77]
    DIRECTION OUTPUT ;
    USE SIGNAL ;
    PORT
      LAYER M4 ;
        RECT  21.408 17.952 21.6 17.976 ;
    END
  END o[77]
  PIN o[78]
    DIRECTION OUTPUT ;
    USE SIGNAL ;
    PORT
      LAYER M4 ;
        RECT  21.408 18.144 21.6 18.168 ;
    END
  END o[78]
  PIN o[79]
    DIRECTION OUTPUT ;
    USE SIGNAL ;
    PORT
      LAYER M4 ;
        RECT  21.408 18.288 21.6 18.312 ;
    END
  END o[79]
  PIN o[7]
    DIRECTION OUTPUT ;
    USE SIGNAL ;
    PORT
      LAYER M4 ;
        RECT  21.408 5.568 21.6 5.592 ;
    END
  END o[7]
  PIN o[80]
    DIRECTION OUTPUT ;
    USE SIGNAL ;
    PORT
      LAYER M4 ;
        RECT  21.408 18.48 21.6 18.504 ;
    END
  END o[80]
  PIN o[81]
    DIRECTION OUTPUT ;
    USE SIGNAL ;
    PORT
      LAYER M4 ;
        RECT  21.408 18.672 21.6 18.696 ;
    END
  END o[81]
  PIN o[82]
    DIRECTION OUTPUT ;
    USE SIGNAL ;
    PORT
      LAYER M4 ;
        RECT  21.408 18.816 21.6 18.84 ;
    END
  END o[82]
  PIN o[83]
    DIRECTION OUTPUT ;
    USE SIGNAL ;
    PORT
      LAYER M4 ;
        RECT  21.408 19.008 21.6 19.032 ;
    END
  END o[83]
  PIN o[84]
    DIRECTION OUTPUT ;
    USE SIGNAL ;
    PORT
      LAYER M4 ;
        RECT  21.408 19.2 21.6 19.224 ;
    END
  END o[84]
  PIN o[85]
    DIRECTION OUTPUT ;
    USE SIGNAL ;
    PORT
      LAYER M4 ;
        RECT  21.408 19.344 21.6 19.368 ;
    END
  END o[85]
  PIN o[86]
    DIRECTION OUTPUT ;
    USE SIGNAL ;
    PORT
      LAYER M4 ;
        RECT  21.408 19.536 21.6 19.56 ;
    END
  END o[86]
  PIN o[87]
    DIRECTION OUTPUT ;
    USE SIGNAL ;
    PORT
      LAYER M4 ;
        RECT  21.408 19.728 21.6 19.752 ;
    END
  END o[87]
  PIN o[88]
    DIRECTION OUTPUT ;
    USE SIGNAL ;
    PORT
      LAYER M4 ;
        RECT  21.408 19.872 21.6 19.896 ;
    END
  END o[88]
  PIN o[89]
    DIRECTION OUTPUT ;
    USE SIGNAL ;
    PORT
      LAYER M4 ;
        RECT  21.408 20.064 21.6 20.088 ;
    END
  END o[89]
  PIN o[8]
    DIRECTION OUTPUT ;
    USE SIGNAL ;
    PORT
      LAYER M4 ;
        RECT  21.408 5.712 21.6 5.736 ;
    END
  END o[8]
  PIN o[90]
    DIRECTION OUTPUT ;
    USE SIGNAL ;
    PORT
      LAYER M4 ;
        RECT  21.408 20.208 21.6 20.232 ;
    END
  END o[90]
  PIN o[91]
    DIRECTION OUTPUT ;
    USE SIGNAL ;
    PORT
      LAYER M4 ;
        RECT  21.408 20.4 21.6 20.424 ;
    END
  END o[91]
  PIN o[92]
    DIRECTION OUTPUT ;
    USE SIGNAL ;
    PORT
      LAYER M4 ;
        RECT  21.408 20.592 21.6 20.616 ;
    END
  END o[92]
  PIN o[93]
    DIRECTION OUTPUT ;
    USE SIGNAL ;
    PORT
      LAYER M4 ;
        RECT  21.408 20.736 21.6 20.76 ;
    END
  END o[93]
  PIN o[94]
    DIRECTION OUTPUT ;
    USE SIGNAL ;
    PORT
      LAYER M4 ;
        RECT  21.408 20.928 21.6 20.952 ;
    END
  END o[94]
  PIN o[95]
    DIRECTION OUTPUT ;
    USE SIGNAL ;
    PORT
      LAYER M4 ;
        RECT  21.408 21.12 21.6 21.144 ;
    END
  END o[95]
  PIN o[96]
    DIRECTION OUTPUT ;
    USE SIGNAL ;
    PORT
      LAYER M4 ;
        RECT  21.408 21.264 21.6 21.288 ;
    END
  END o[96]
  PIN o[97]
    DIRECTION OUTPUT ;
    USE SIGNAL ;
    PORT
      LAYER M4 ;
        RECT  21.408 21.456 21.6 21.48 ;
    END
  END o[97]
  PIN o[98]
    DIRECTION OUTPUT ;
    USE SIGNAL ;
    PORT
      LAYER M4 ;
        RECT  21.408 21.648 21.6 21.672 ;
    END
  END o[98]
  PIN o[99]
    DIRECTION OUTPUT ;
    USE SIGNAL ;
    PORT
      LAYER M4 ;
        RECT  21.408 21.792 21.6 21.816 ;
    END
  END o[99]
  PIN o[9]
    DIRECTION OUTPUT ;
    USE SIGNAL ;
    PORT
      LAYER M4 ;
        RECT  21.408 5.904 21.6 5.928 ;
    END
  END o[9]
  PIN rs
    DIRECTION INPUT ;
    USE SIGNAL ;
    PORT
      LAYER M5 ;
        RECT  10.8 0 10.824 0.192 ;
    END
    PORT
      LAYER M5 ;
        RECT  10.8 0.144 10.824 1.763 ;
    END
  END rs
  PIN VDD
    DIRECTION INOUT ;
    USE POWER ;
    PORT
      LAYER M5 ;
        RECT  18.792 2.151 18.912 30.249 ;
        RECT  16.092 2.151 16.212 30.249 ;
        RECT  13.392 2.151 13.512 30.249 ;
        RECT  10.692 2.151 10.812 30.249 ;
        RECT  7.992 2.151 8.112 30.249 ;
        RECT  5.292 2.151 5.412 30.249 ;
        RECT  2.592 2.151 2.712 30.249 ;
    END
  END VDD
  PIN VSS
    DIRECTION INOUT ;
    USE GROUND ;
    PORT
      LAYER M5 ;
        RECT  18.6 2.137 18.72 30.263 ;
        RECT  15.9 2.137 16.02 30.263 ;
        RECT  13.2 2.137 13.32 30.263 ;
        RECT  10.5 2.137 10.62 30.263 ;
        RECT  7.8 2.137 7.92 30.263 ;
        RECT  5.1 2.137 5.22 30.263 ;
        RECT  2.4 2.137 2.52 30.263 ;
    END
  END VSS
  # OT_OBS_CLOSED layer=M5 d_um=1.536 added=3
  OBS
    LAYER RVTN ;
     RECT  2.16 2.16 19.44 2.295 ;
     RECT  2.16 2.565 19.44 2.835 ;
     RECT  2.16 3.105 19.44 3.375 ;
     RECT  2.16 3.645 19.44 3.915 ;
     RECT  2.16 4.185 19.44 4.455 ;
     RECT  2.16 4.725 19.44 4.995 ;
     RECT  2.16 5.265 19.44 5.535 ;
     RECT  2.16 5.805 19.44 6.075 ;
     RECT  2.16 6.345 19.44 6.615 ;
     RECT  2.16 6.885 19.44 7.155 ;
     RECT  2.16 7.425 19.44 7.695 ;
     RECT  2.16 7.965 19.44 8.235 ;
     RECT  2.16 8.505 19.44 8.775 ;
     RECT  2.16 9.045 19.44 9.315 ;
     RECT  2.16 9.585 19.44 9.855 ;
     RECT  2.16 10.125 19.44 10.395 ;
     RECT  2.16 10.665 19.44 10.935 ;
     RECT  2.16 11.205 19.44 11.475 ;
     RECT  2.16 11.745 19.44 12.015 ;
     RECT  2.16 12.285 19.44 12.555 ;
     RECT  2.16 12.825 19.44 13.095 ;
     RECT  2.16 13.365 19.44 13.635 ;
     RECT  2.16 13.905 19.44 14.175 ;
     RECT  2.16 14.445 19.44 14.715 ;
     RECT  2.16 14.985 19.44 15.255 ;
     RECT  2.16 15.525 19.44 15.795 ;
     RECT  2.16 16.065 19.44 16.335 ;
     RECT  2.16 16.605 19.44 16.875 ;
     RECT  2.16 17.145 19.44 17.415 ;
     RECT  2.16 17.685 19.44 17.955 ;
     RECT  2.16 18.225 19.44 18.495 ;
     RECT  2.16 18.765 19.44 19.035 ;
     RECT  2.16 19.305 19.44 19.575 ;
     RECT  2.16 19.845 19.44 20.115 ;
     RECT  2.16 20.385 19.44 20.655 ;
     RECT  2.16 20.925 19.44 21.195 ;
     RECT  2.16 21.465 19.44 21.735 ;
     RECT  2.16 22.005 19.44 22.275 ;
     RECT  2.16 22.545 19.44 22.815 ;
     RECT  2.16 23.085 19.44 23.355 ;
     RECT  2.16 23.625 19.44 23.895 ;
     RECT  2.16 24.165 19.44 24.435 ;
     RECT  2.16 24.705 19.44 24.975 ;
     RECT  2.16 25.245 19.44 25.515 ;
     RECT  2.16 25.785 19.44 26.055 ;
     RECT  2.16 26.325 19.44 26.595 ;
     RECT  2.16 26.865 19.44 27.135 ;
     RECT  2.16 27.405 19.44 27.675 ;
     RECT  2.16 27.945 19.44 28.215 ;
     RECT  2.16 28.485 19.44 28.755 ;
     RECT  2.16 29.025 19.44 29.295 ;
     RECT  2.16 29.565 19.44 29.835 ;
     RECT  2.16 30.105 19.44 30.24 ;
    LAYER RVTP ;
     RECT  2.16 2.295 19.44 2.565 ;
     RECT  2.16 2.835 19.44 3.105 ;
     RECT  2.16 3.375 19.44 3.645 ;
     RECT  2.16 3.915 19.44 4.185 ;
     RECT  2.16 4.455 19.44 4.725 ;
     RECT  2.16 4.995 19.44 5.265 ;
     RECT  2.16 5.535 19.44 5.805 ;
     RECT  2.16 6.075 19.44 6.345 ;
     RECT  2.16 6.615 19.44 6.885 ;
     RECT  2.16 7.155 19.44 7.425 ;
     RECT  2.16 7.695 19.44 7.965 ;
     RECT  2.16 8.235 19.44 8.505 ;
     RECT  2.16 8.775 19.44 9.045 ;
     RECT  2.16 9.315 19.44 9.585 ;
     RECT  2.16 9.855 19.44 10.125 ;
     RECT  2.16 10.395 19.44 10.665 ;
     RECT  2.16 10.935 19.44 11.205 ;
     RECT  2.16 11.475 19.44 11.745 ;
     RECT  2.16 12.015 19.44 12.285 ;
     RECT  2.16 12.555 19.44 12.825 ;
     RECT  2.16 13.095 19.44 13.365 ;
     RECT  2.16 13.635 19.44 13.905 ;
     RECT  2.16 14.175 19.44 14.445 ;
     RECT  2.16 14.715 19.44 14.985 ;
     RECT  2.16 15.255 19.44 15.525 ;
     RECT  2.16 15.795 19.44 16.065 ;
     RECT  2.16 16.335 19.44 16.605 ;
     RECT  2.16 16.875 19.44 17.145 ;
     RECT  2.16 17.415 19.44 17.685 ;
     RECT  2.16 17.955 19.44 18.225 ;
     RECT  2.16 18.495 19.44 18.765 ;
     RECT  2.16 19.035 19.44 19.305 ;
     RECT  2.16 19.575 19.44 19.845 ;
     RECT  2.16 20.115 19.44 20.385 ;
     RECT  2.16 20.655 19.44 20.925 ;
     RECT  2.16 21.195 19.44 21.465 ;
     RECT  2.16 21.735 19.44 22.005 ;
     RECT  2.16 22.275 19.44 22.545 ;
     RECT  2.16 22.815 19.44 23.085 ;
     RECT  2.16 23.355 19.44 23.625 ;
     RECT  2.16 23.895 19.44 24.165 ;
     RECT  2.16 24.435 19.44 24.705 ;
     RECT  2.16 24.975 19.44 25.245 ;
     RECT  2.16 25.515 19.44 25.785 ;
     RECT  2.16 26.055 19.44 26.325 ;
     RECT  2.16 26.595 19.44 26.865 ;
     RECT  2.16 27.135 19.44 27.405 ;
     RECT  2.16 27.675 19.44 27.945 ;
     RECT  2.16 28.215 19.44 28.485 ;
     RECT  2.16 28.755 19.44 29.025 ;
     RECT  2.16 29.295 19.44 29.565 ;
     RECT  2.16 29.835 19.44 30.105 ;
    LAYER M1 ;
     RECT  2.16 2.151 19.44 30.249 ;
    LAYER M2 ;
     RECT  0.211 3.312 0.247 3.33 ;
     RECT  0.211 22.59 0.499 22.608 ;
     RECT  0.211 11.952 0.535 11.97 ;
     RECT  0.211 13.068 0.535 13.086 ;
     RECT  0.499 22.59 0.535 23.184 ;
     RECT  0.211 24.48 0.535 24.498 ;
     RECT  0.247 3.312 2.16 3.978 ;
     RECT  0.535 5.31 2.16 5.328 ;
     RECT  0.211 6.552 2.16 6.57 ;
     RECT  0.535 11.952 2.16 13.086 ;
     RECT  0.211 14.49 2.16 14.508 ;
     RECT  0.211 16.92 2.16 17.676 ;
     RECT  0.211 18.702 2.16 18.72 ;
     RECT  0.211 20.97 2.16 20.988 ;
     RECT  0.535 22.086 2.16 24.498 ;
     RECT  0.211 27.342 2.16 27.36 ;
     RECT  2.16 2.151 19.44 30.249 ;
     RECT  19.44 4.086 19.463 28.134 ;
     RECT  19.463 13.266 19.967 28.134 ;
     RECT  19.463 4.086 20.543 12.24 ;
     RECT  19.967 13.266 20.543 16.02 ;
     RECT  19.967 16.776 20.543 28.134 ;
     RECT  20.543 4.086 20.579 4.104 ;
     RECT  20.543 5.436 20.579 5.454 ;
     RECT  20.543 12.222 20.579 12.24 ;
     RECT  20.543 14.616 20.579 14.634 ;
     RECT  20.543 15.732 20.579 15.75 ;
     RECT  20.543 23.976 20.579 23.994 ;
     RECT  20.543 25.686 20.579 25.704 ;
     RECT  21.379 16.272 21.479 16.29 ;
     RECT  21.379 17.811 21.479 17.829 ;
    LAYER M3 ;
     RECT  10.44 1.723 10.458 2.143 ;
     RECT  10.44 2.143 10.605 2.371 ;
     RECT  2.415 2.143 2.505 2.413 ;
     RECT  5.115 2.143 5.205 2.413 ;
     RECT  7.815 2.143 7.905 2.413 ;
     RECT  10.188 2.371 10.605 2.413 ;
     RECT  13.215 2.143 13.305 2.413 ;
     RECT  15.915 2.143 16.005 2.413 ;
     RECT  18.615 2.143 18.705 2.413 ;
     RECT  2.415 2.413 2.697 3.271 ;
     RECT  2.376 3.271 2.697 3.721 ;
     RECT  2.34 3.721 2.697 3.883 ;
     RECT  0.216 3.307 0.234 3.955 ;
     RECT  10.188 2.413 10.797 3.991 ;
     RECT  7.815 2.413 8.097 4.081 ;
     RECT  5.115 2.413 5.397 4.117 ;
     RECT  7.632 4.081 8.19 4.117 ;
     RECT  5.115 4.117 5.67 4.153 ;
     RECT  7.632 4.117 8.838 4.153 ;
     RECT  5.115 4.153 5.742 4.189 ;
     RECT  2.34 3.883 2.826 4.261 ;
     RECT  7.632 4.153 8.946 4.261 ;
     RECT  9.756 3.991 10.797 4.261 ;
     RECT  20.556 4.081 20.574 4.315 ;
     RECT  0.216 3.955 0.27 4.349 ;
     RECT  4.824 4.189 5.742 4.387 ;
     RECT  4.176 4.387 5.742 4.495 ;
     RECT  2.34 4.261 3.006 4.507 ;
     RECT  2.304 4.507 3.006 4.531 ;
     RECT  4.068 4.495 5.742 4.531 ;
     RECT  7.632 4.261 10.797 4.531 ;
     RECT  20.52 4.315 20.574 4.541 ;
     RECT  7.632 4.531 11.214 4.649 ;
     RECT  6.84 4.495 6.858 4.693 ;
     RECT  6.804 4.693 6.858 4.729 ;
     RECT  7.632 4.649 9.126 4.729 ;
     RECT  6.804 4.729 9.126 4.793 ;
     RECT  2.304 4.531 5.742 4.801 ;
     RECT  6.804 4.793 8.982 4.801 ;
     RECT  10.008 4.649 11.214 4.801 ;
     RECT  10.008 4.801 11.646 4.919 ;
     RECT  20.52 4.541 20.538 4.927 ;
     RECT  10.008 4.919 11.43 4.991 ;
     RECT  13.215 2.413 13.497 5.035 ;
     RECT  0.252 4.349 0.27 5.069 ;
     RECT  19.944 4.927 20.538 5.069 ;
     RECT  2.304 4.801 8.982 5.189 ;
     RECT  12.528 5.035 13.497 5.189 ;
     RECT  14.436 4.891 14.454 5.197 ;
     RECT  2.304 5.189 5.397 5.261 ;
     RECT  14.436 5.197 14.814 5.297 ;
     RECT  20.484 5.069 20.538 5.431 ;
     RECT  20.484 5.431 20.574 5.597 ;
     RECT  6.156 5.189 8.982 5.611 ;
     RECT  6.156 5.611 9.162 5.737 ;
     RECT  10.224 4.991 11.322 5.737 ;
     RECT  15.915 2.413 16.197 5.737 ;
     RECT  14.436 5.297 14.454 5.801 ;
     RECT  15.336 5.737 16.197 5.909 ;
     RECT  20.484 5.597 20.538 5.933 ;
     RECT  4.824 5.261 5.397 5.971 ;
     RECT  6.156 5.737 11.322 5.971 ;
     RECT  4.824 5.971 11.646 5.999 ;
     RECT  10.224 5.999 11.646 6.007 ;
     RECT  0.54 5.305 0.558 6.125 ;
     RECT  2.304 5.261 4.05 6.151 ;
     RECT  4.824 5.999 8.982 6.151 ;
     RECT  10.224 6.007 12.222 6.179 ;
     RECT  2.304 6.151 8.982 6.269 ;
     RECT  10.224 6.179 12.15 6.413 ;
     RECT  14.508 6.511 15.138 6.647 ;
     RECT  14.508 6.647 15.03 6.683 ;
     RECT  7.092 6.269 8.982 6.781 ;
     RECT  10.224 6.413 12.114 6.781 ;
     RECT  7.092 6.781 12.114 6.881 ;
     RECT  13.215 5.189 13.497 6.925 ;
     RECT  0.216 6.547 0.234 6.989 ;
     RECT  15.915 5.909 16.197 7.051 ;
     RECT  20.52 5.933 20.538 7.051 ;
     RECT  13.215 6.925 14.13 7.079 ;
     RECT  15.915 7.051 16.398 7.087 ;
     RECT  19.944 7.051 20.538 7.133 ;
     RECT  7.092 6.881 9.486 7.151 ;
     RECT  10.476 6.881 11.142 7.151 ;
     RECT  12.06 6.881 12.114 7.151 ;
     RECT  14.868 6.683 15.03 7.151 ;
     RECT  15.915 7.087 16.686 7.187 ;
     RECT  2.304 6.269 6.354 7.231 ;
     RECT  7.092 7.151 8.946 7.231 ;
     RECT  13.215 7.079 13.626 7.231 ;
     RECT  12.636 7.231 13.626 7.349 ;
     RECT  14.868 7.151 14.886 7.349 ;
     RECT  10.515 7.151 10.998 7.421 ;
     RECT  20.484 7.133 20.538 7.517 ;
     RECT  12.78 7.349 13.626 7.529 ;
     RECT  18.615 2.413 18.897 7.819 ;
     RECT  15.915 7.187 16.197 7.861 ;
     RECT  12.78 7.529 13.497 7.889 ;
     RECT  18.615 7.819 18.99 7.889 ;
     RECT  0.216 7.819 0.234 7.949 ;
     RECT  11.772 7.861 11.79 7.961 ;
     RECT  15.66 7.861 16.197 7.961 ;
     RECT  17.676 7.861 17.694 7.961 ;
     RECT  10.515 7.421 10.89 8.131 ;
     RECT  10.224 8.131 10.89 8.231 ;
     RECT  15.084 8.131 15.102 8.231 ;
     RECT  10.515 8.231 10.89 8.239 ;
     RECT  2.304 7.231 8.946 8.267 ;
     RECT  13.176 7.889 13.497 8.311 ;
     RECT  14.796 8.239 14.85 8.311 ;
     RECT  10.515 8.239 11.43 8.429 ;
     RECT  20.52 7.517 20.538 8.437 ;
     RECT  10.515 8.429 11.286 8.573 ;
     RECT  20.484 8.437 20.538 8.573 ;
     RECT  7.2 8.267 8.946 8.581 ;
     RECT  2.304 8.267 6.462 8.683 ;
     RECT  7.2 8.581 9.306 8.699 ;
     RECT  13.176 8.311 14.85 8.717 ;
     RECT  14.832 8.717 14.85 8.813 ;
     RECT  2.268 8.683 6.462 9.005 ;
     RECT  13.176 8.717 14.022 9.041 ;
     RECT  13.176 9.041 13.518 9.067 ;
     RECT  2.304 9.005 6.462 9.121 ;
     RECT  7.2 8.699 8.946 9.121 ;
     RECT  12.708 9.067 13.518 9.211 ;
     RECT  12.492 9.211 13.518 9.311 ;
     RECT  17.136 9.211 17.154 9.311 ;
     RECT  0.216 9.211 0.234 9.341 ;
     RECT  12.636 9.311 13.518 9.509 ;
     RECT  10.515 8.573 10.818 9.517 ;
     RECT  15.915 7.961 16.197 9.517 ;
     RECT  10.044 9.517 10.818 9.553 ;
     RECT  12.672 9.509 13.518 9.653 ;
     RECT  10.044 9.553 10.926 9.689 ;
     RECT  15.768 9.517 16.197 9.689 ;
     RECT  10.515 9.689 10.926 9.751 ;
     RECT  11.772 9.481 11.79 9.751 ;
     RECT  12.96 9.653 13.518 9.779 ;
     RECT  2.304 9.121 8.946 9.859 ;
     RECT  14.724 9.787 14.742 9.859 ;
     RECT  14.724 9.859 14.814 9.959 ;
     RECT  12.96 9.779 13.497 10.049 ;
     RECT  2.304 9.859 9.666 10.121 ;
     RECT  10.515 9.751 11.79 10.291 ;
     RECT  17.46 10.291 17.478 10.363 ;
     RECT  10.515 10.291 11.97 10.391 ;
     RECT  17.46 10.363 17.55 10.391 ;
     RECT  10.515 10.391 11.574 10.463 ;
     RECT  10.515 10.463 11.214 10.471 ;
     RECT  17.532 10.391 17.55 10.499 ;
     RECT  20.52 8.573 20.538 10.561 ;
     RECT  2.304 10.121 8.91 10.705 ;
     RECT  2.268 10.705 8.91 10.829 ;
     RECT  13.176 10.049 13.497 10.831 ;
     RECT  9.792 10.471 11.214 10.859 ;
     RECT  18.615 7.889 18.897 10.867 ;
     RECT  12.744 10.831 13.497 10.931 ;
     RECT  14.832 10.363 14.85 10.967 ;
     RECT  15.915 9.689 16.197 11.209 ;
     RECT  9.864 10.859 11.214 11.273 ;
     RECT  14.868 11.011 14.886 11.273 ;
     RECT  15.915 11.209 16.866 11.281 ;
     RECT  10.224 11.273 11.214 11.399 ;
     RECT  15.915 11.281 17.262 11.399 ;
     RECT  18.216 10.867 18.897 11.471 ;
     RECT  19.944 10.561 20.538 11.501 ;
     RECT  10.515 11.399 11.214 11.911 ;
     RECT  18.615 11.471 18.897 11.911 ;
     RECT  2.304 10.829 8.91 11.947 ;
     RECT  17.748 11.821 17.766 11.975 ;
     RECT  15.915 11.399 16.722 12.011 ;
     RECT  2.232 11.947 8.91 12.019 ;
     RECT  2.232 12.019 9.594 12.047 ;
     RECT  14.76 11.785 14.85 12.181 ;
     RECT  2.304 12.047 9.594 12.209 ;
     RECT  10.515 11.911 11.97 12.209 ;
     RECT  10.515 12.209 11.25 12.217 ;
     RECT  14.544 12.181 14.85 12.217 ;
     RECT  20.52 11.501 20.538 12.217 ;
     RECT  20.52 12.217 20.574 12.221 ;
     RECT  2.304 12.209 8.946 12.245 ;
     RECT  10.476 12.217 11.25 12.281 ;
     RECT  14.544 12.217 15.03 12.281 ;
     RECT  0.216 11.947 0.234 12.361 ;
     RECT  10.476 12.281 11.214 12.389 ;
     RECT  15.012 12.281 15.03 12.389 ;
     RECT  20.556 12.221 20.574 12.413 ;
     RECT  11.988 12.361 12.006 12.479 ;
     RECT  13.215 10.931 13.497 12.523 ;
     RECT  12.816 12.523 13.497 12.56 ;
     RECT  10.515 12.389 11.214 12.587 ;
     RECT  17.244 12.631 17.262 12.721 ;
     RECT  0.216 12.361 0.558 12.749 ;
     RECT  9.756 12.631 9.774 12.749 ;
     RECT  17.244 12.721 17.73 12.893 ;
     RECT  15.915 12.011 16.197 12.901 ;
     RECT  18.615 11.911 19.422 12.901 ;
     RECT  18.615 12.901 19.458 12.991 ;
     RECT  15.84 12.901 16.398 13.019 ;
     RECT  17.244 12.893 17.262 13.019 ;
     RECT  18.216 12.991 19.458 13.085 ;
     RECT  18.216 13.085 18.99 13.091 ;
     RECT  14.328 13.171 14.346 13.325 ;
     RECT  10.515 12.587 10.797 13.369 ;
     RECT  2.304 12.245 8.91 13.405 ;
     RECT  13.215 12.56 13.497 13.441 ;
     RECT  0.216 12.749 0.234 13.469 ;
     RECT  2.304 13.405 9.306 13.559 ;
     RECT  12.528 13.441 13.497 13.559 ;
     RECT  13.032 13.559 13.497 13.595 ;
     RECT  14.436 13.369 15.066 13.631 ;
     RECT  10.515 13.369 10.818 13.639 ;
     RECT  11.736 13.261 11.754 13.639 ;
     RECT  14.796 13.631 15.066 13.639 ;
     RECT  15.84 13.019 16.197 13.639 ;
     RECT  14.796 13.639 16.197 13.709 ;
     RECT  13.068 13.595 13.497 13.829 ;
     RECT  14.796 13.709 14.886 13.937 ;
     RECT  10.515 13.639 11.754 13.945 ;
     RECT  14.832 13.937 14.886 13.973 ;
     RECT  18.54 13.091 18.99 13.981 ;
     RECT  18.54 13.981 19.422 14.071 ;
     RECT  10.515 13.945 12.042 14.171 ;
     RECT  14.868 13.973 14.886 14.207 ;
     RECT  18.18 14.071 19.422 14.243 ;
     RECT  0.252 14.299 0.27 14.429 ;
     RECT  18.615 14.243 19.422 14.483 ;
     RECT  15.876 13.709 16.197 14.485 ;
     RECT  20.52 13.243 20.538 14.611 ;
     RECT  15.696 14.485 16.197 14.639 ;
     RECT  10.515 14.171 11.646 14.711 ;
     RECT  15.768 14.639 16.197 14.711 ;
     RECT  10.515 14.711 10.854 14.783 ;
     RECT  2.304 13.559 8.982 14.791 ;
     RECT  2.304 14.791 9.306 14.819 ;
     RECT  0.216 14.485 0.234 14.861 ;
     RECT  20.52 14.611 20.574 14.861 ;
     RECT  5.115 14.819 9.306 15.016 ;
     RECT  5.115 15.016 9.342 15.053 ;
     RECT  13.215 13.829 13.497 15.061 ;
     RECT  12.888 15.061 13.497 15.179 ;
     RECT  18.615 14.483 18.897 15.295 ;
     RECT  10.515 14.783 10.797 15.331 ;
     RECT  18.615 15.295 18.99 15.389 ;
     RECT  14.22 15.151 14.238 15.421 ;
     RECT  10.116 15.331 10.797 15.449 ;
     RECT  11.736 15.307 12.222 15.449 ;
     RECT  15.915 14.711 16.197 15.457 ;
     RECT  11.736 15.449 11.754 15.521 ;
     RECT  13.215 15.179 13.497 15.691 ;
     RECT  14.22 15.421 14.886 15.691 ;
     RECT  5.115 15.053 9.018 15.719 ;
     RECT  20.52 14.861 20.538 15.724 ;
     RECT  2.304 14.819 4.194 15.739 ;
     RECT  5.115 15.719 8.874 15.739 ;
     RECT  13.215 15.691 14.886 15.791 ;
     RECT  15.66 15.457 16.197 15.835 ;
     RECT  20.52 15.724 20.574 15.869 ;
     RECT  13.215 15.791 13.497 15.961 ;
     RECT  2.304 15.739 8.874 15.989 ;
     RECT  10.224 15.449 10.797 15.989 ;
     RECT  14.904 15.835 16.197 16.061 ;
     RECT  15.372 16.061 16.197 16.097 ;
     RECT  10.515 15.989 10.797 16.105 ;
     RECT  11.7 15.961 11.718 16.133 ;
     RECT  15.915 16.097 16.197 16.267 ;
     RECT  20.52 15.869 20.538 16.267 ;
     RECT  21.384 16.219 21.402 16.267 ;
     RECT  21.384 16.267 21.474 16.295 ;
     RECT  21.456 16.295 21.474 16.304 ;
     RECT  0.324 16.219 0.342 16.349 ;
     RECT  9.684 16.303 9.702 16.349 ;
     RECT  15.915 16.267 16.758 16.439 ;
     RECT  10.515 16.105 10.854 16.501 ;
     RECT  10.515 16.501 11.394 16.589 ;
     RECT  10.515 16.589 11.286 16.673 ;
     RECT  10.515 16.673 10.926 16.771 ;
     RECT  12.924 15.961 13.497 16.771 ;
     RECT  9.9 16.771 10.926 16.943 ;
     RECT  12.384 16.771 13.497 16.943 ;
     RECT  9.9 16.943 10.854 16.979 ;
     RECT  10.476 16.979 10.854 17.069 ;
     RECT  2.304 15.989 8.586 17.077 ;
     RECT  19.944 16.267 20.538 17.117 ;
     RECT  15.048 17.041 15.066 17.213 ;
     RECT  15.915 16.439 16.326 17.249 ;
     RECT  2.304 17.077 8.838 17.311 ;
     RECT  16.92 17.311 16.938 17.411 ;
     RECT  18.615 15.389 18.897 17.419 ;
     RECT  2.304 17.311 8.91 17.491 ;
     RECT  17.748 17.455 17.766 17.491 ;
     RECT  10.515 17.069 10.854 17.519 ;
     RECT  18.615 17.419 18.954 17.519 ;
     RECT  14.832 17.419 14.994 17.581 ;
     RECT  2.304 17.491 9.594 17.609 ;
     RECT  17.208 17.491 17.766 17.609 ;
     RECT  13.215 16.943 13.497 17.617 ;
     RECT  14.76 17.581 14.994 17.681 ;
     RECT  17.208 17.609 17.226 17.681 ;
     RECT  14.796 17.681 14.994 17.693 ;
     RECT  21.456 17.755 21.474 17.8 ;
     RECT  21.384 17.8 21.474 17.834 ;
     RECT  0.216 16.363 0.234 17.837 ;
     RECT  21.384 17.834 21.402 17.837 ;
     RECT  13.215 17.617 13.662 17.879 ;
     RECT  10.515 17.519 10.797 17.995 ;
     RECT  14.796 17.693 14.814 18.059 ;
     RECT  10.332 17.995 10.797 18.121 ;
     RECT  12.096 17.491 12.114 18.121 ;
     RECT  11.664 18.121 12.186 18.221 ;
     RECT  10.116 18.121 10.797 18.391 ;
     RECT  11.664 18.221 11.97 18.391 ;
     RECT  18.615 17.519 18.897 18.391 ;
     RECT  15.915 17.249 16.197 18.427 ;
     RECT  10.116 18.391 11.97 18.491 ;
     RECT  18.615 18.391 19.422 18.509 ;
     RECT  10.116 18.491 10.854 18.571 ;
     RECT  15.915 18.427 16.218 18.571 ;
     RECT  11.88 18.491 11.97 18.599 ;
     RECT  9.792 18.571 10.854 18.689 ;
     RECT  15.228 18.571 17.046 18.689 ;
     RECT  18.615 18.509 18.99 18.701 ;
     RECT  11.952 18.599 11.97 18.725 ;
     RECT  17.028 18.689 17.046 18.725 ;
     RECT  15.228 18.689 16.197 18.761 ;
     RECT  20.52 17.117 20.538 18.769 ;
     RECT  19.944 18.769 20.538 18.845 ;
     RECT  0.216 18.697 0.234 19.037 ;
     RECT  2.304 17.609 8.838 19.039 ;
     RECT  2.304 19.039 9.342 19.301 ;
     RECT  17.316 19.201 17.334 19.373 ;
     RECT  18.615 18.701 18.897 19.381 ;
     RECT  18.144 19.381 18.897 19.471 ;
     RECT  17.676 19.471 18.897 19.499 ;
     RECT  17.676 19.499 17.694 19.571 ;
     RECT  13.215 17.879 13.497 19.615 ;
     RECT  10.515 18.689 10.797 19.741 ;
     RECT  15.915 18.761 16.197 19.741 ;
     RECT  20.52 18.845 20.538 19.768 ;
     RECT  15.444 19.741 16.197 19.949 ;
     RECT  12.348 19.651 12.366 20.191 ;
     RECT  13.212 19.615 13.497 20.191 ;
     RECT  12.348 20.191 13.497 20.281 ;
     RECT  11.952 20.281 13.497 20.309 ;
     RECT  2.304 19.301 8.91 20.317 ;
     RECT  14.328 20.281 14.346 20.317 ;
     RECT  14.328 20.317 14.922 20.381 ;
     RECT  20.484 19.768 20.538 20.429 ;
     RECT  14.832 20.381 14.922 20.489 ;
     RECT  2.304 20.317 8.946 20.731 ;
     RECT  11.952 20.309 12.006 20.759 ;
     RECT  2.304 20.731 9.198 20.849 ;
     RECT  2.304 20.849 8.91 20.885 ;
     RECT  11.52 20.821 11.538 20.921 ;
     RECT  10.296 19.741 10.797 21.029 ;
     RECT  14.832 20.489 14.85 21.029 ;
     RECT  10.515 21.029 10.797 21.091 ;
     RECT  0.216 20.965 0.234 21.149 ;
     RECT  10.515 21.091 11.43 21.191 ;
     RECT  15.915 19.949 16.197 21.271 ;
     RECT  15.84 21.271 16.197 21.361 ;
     RECT  13.215 20.309 13.497 21.433 ;
     RECT  20.52 20.429 20.538 21.451 ;
     RECT  14.688 21.361 14.706 21.461 ;
     RECT  12.78 21.433 13.497 21.541 ;
     RECT  2.304 20.885 8.874 21.643 ;
     RECT  19.944 21.451 20.538 21.677 ;
     RECT  10.515 21.191 10.854 21.811 ;
     RECT  12.708 21.541 13.497 21.811 ;
     RECT  12.708 21.811 13.842 21.901 ;
     RECT  15.624 21.361 16.197 21.901 ;
     RECT  10.332 21.811 10.854 21.929 ;
     RECT  20.484 21.677 20.538 21.938 ;
     RECT  12.312 21.901 13.842 21.965 ;
     RECT  12.312 21.965 12.33 22.001 ;
     RECT  15.192 21.901 16.197 22.001 ;
     RECT  2.268 21.643 8.874 22.009 ;
     RECT  2.268 22.009 9.342 22.061 ;
     RECT  13.068 21.965 13.842 22.081 ;
     RECT  13.068 22.081 14.022 22.109 ;
     RECT  10.515 21.929 10.854 22.171 ;
     RECT  13.14 22.109 14.022 22.207 ;
     RECT  13.14 22.207 14.238 22.235 ;
     RECT  2.268 22.061 8.838 22.307 ;
     RECT  10.515 22.171 12.078 22.343 ;
     RECT  13.215 22.235 14.238 22.349 ;
     RECT  15.084 22.351 15.102 22.477 ;
     RECT  15.84 22.001 16.197 22.477 ;
     RECT  10.515 22.343 11.034 22.541 ;
     RECT  11.844 22.343 12.078 22.541 ;
     RECT  15.84 22.477 16.542 22.577 ;
     RECT  0.54 22.081 0.558 22.585 ;
     RECT  18.615 19.499 18.897 22.621 ;
     RECT  0.216 22.585 0.558 22.685 ;
     RECT  18.615 22.621 19.422 22.685 ;
     RECT  9.648 22.315 9.666 22.739 ;
     RECT  14.832 22.477 15.102 22.739 ;
     RECT  12.06 22.541 12.078 22.811 ;
     RECT  13.215 22.349 13.806 22.877 ;
     RECT  15.84 22.577 16.197 22.891 ;
     RECT  17.244 22.981 17.262 23.081 ;
     RECT  14.832 22.739 14.85 23.153 ;
     RECT  10.515 22.541 10.797 23.323 ;
     RECT  10.26 23.323 11.322 23.521 ;
     RECT  0.216 22.685 0.522 23.597 ;
     RECT  9.936 23.521 11.322 23.621 ;
     RECT  12.24 23.521 12.258 23.791 ;
     RECT  13.215 22.877 13.497 23.791 ;
     RECT  20.52 21.938 20.538 23.818 ;
     RECT  14.724 23.701 14.742 23.819 ;
     RECT  12.24 23.791 13.497 23.891 ;
     RECT  0.504 23.597 0.522 23.899 ;
     RECT  20.484 23.818 20.538 23.933 ;
     RECT  2.304 22.307 8.838 23.971 ;
     RECT  10.224 23.621 11.322 23.971 ;
     RECT  20.52 23.933 20.538 23.971 ;
     RECT  15.732 22.891 16.197 24.061 ;
     RECT  10.224 23.971 11.79 24.089 ;
     RECT  0.504 23.899 0.558 24.125 ;
     RECT  14.364 24.061 14.382 24.161 ;
     RECT  2.304 23.971 8.874 24.205 ;
     RECT  0.504 24.125 0.522 24.269 ;
     RECT  10.224 24.089 11.682 24.269 ;
     RECT  20.52 23.971 20.574 24.269 ;
     RECT  2.304 24.205 9.486 24.467 ;
     RECT  10.515 24.269 11.682 24.701 ;
     RECT  18.615 22.685 18.897 24.763 ;
     RECT  10.515 24.701 11.502 24.899 ;
     RECT  18.615 24.763 19.422 24.899 ;
     RECT  2.304 24.467 9.342 24.971 ;
     RECT  15.336 24.061 16.197 24.979 ;
     RECT  13.215 23.891 13.497 25.141 ;
     RECT  20.52 24.269 20.538 25.177 ;
     RECT  12.816 25.141 13.497 25.241 ;
     RECT  19.944 25.177 20.538 25.325 ;
     RECT  14.832 24.979 16.197 25.411 ;
     RECT  2.304 24.971 9.306 25.439 ;
     RECT  13.14 25.241 13.497 25.439 ;
     RECT  14.364 25.411 16.197 25.511 ;
     RECT  0.216 24.475 0.234 25.517 ;
     RECT  14.724 25.511 15.102 25.613 ;
     RECT  18.615 24.899 18.99 25.661 ;
     RECT  10.515 24.899 11.322 25.681 ;
     RECT  20.52 25.325 20.538 25.681 ;
     RECT  10.515 25.681 11.466 25.781 ;
     RECT  10.515 25.781 11.286 25.979 ;
     RECT  20.52 25.681 20.574 26.045 ;
     RECT  10.515 25.979 11.25 26.131 ;
     RECT  2.304 25.439 8.946 26.249 ;
     RECT  15.084 25.613 15.102 26.321 ;
     RECT  10.044 26.131 11.25 26.429 ;
     RECT  2.304 26.249 8.91 26.491 ;
     RECT  10.188 26.429 11.25 26.591 ;
     RECT  13.215 25.439 13.497 26.671 ;
     RECT  15.915 25.511 16.197 26.761 ;
     RECT  12.708 26.671 13.497 26.789 ;
     RECT  2.268 26.491 8.91 26.825 ;
     RECT  15.228 26.761 16.197 26.909 ;
     RECT  14.22 26.905 14.238 27.031 ;
     RECT  14.22 27.031 14.31 27.131 ;
     RECT  10.515 26.591 11.25 27.301 ;
     RECT  10.515 27.301 11.862 27.337 ;
     RECT  14.796 27.211 14.814 27.365 ;
     RECT  10.368 27.337 12.078 27.401 ;
     RECT  12.06 27.401 12.078 27.437 ;
     RECT  2.304 26.825 8.91 27.547 ;
     RECT  10.368 27.401 11.286 27.599 ;
     RECT  18.615 25.661 18.897 27.643 ;
     RECT  2.268 27.547 8.91 27.691 ;
     RECT  13.215 26.789 13.497 27.739 ;
     RECT  14.832 27.643 14.85 27.773 ;
     RECT  18.615 27.643 18.99 27.773 ;
     RECT  2.268 27.691 9.198 27.905 ;
     RECT  2.304 27.905 9.198 27.913 ;
     RECT  10.368 27.599 11.214 27.913 ;
     RECT  13.215 27.739 13.59 27.917 ;
     RECT  2.304 27.913 11.214 27.965 ;
     RECT  2.304 27.965 10.998 28.139 ;
     RECT  20.52 26.045 20.538 28.139 ;
     RECT  2.304 28.139 8.838 28.175 ;
     RECT  0.216 27.337 0.234 28.253 ;
     RECT  2.304 28.175 3.69 28.283 ;
     RECT  4.5 28.175 8.154 28.283 ;
     RECT  4.5 28.283 5.397 28.409 ;
     RECT  6.156 28.283 8.154 28.409 ;
     RECT  9.864 28.139 10.998 28.409 ;
     RECT  6.228 28.409 8.097 28.445 ;
     RECT  6.408 28.445 8.097 28.787 ;
     RECT  6.408 28.787 6.426 28.823 ;
     RECT  7.236 28.787 8.097 28.823 ;
     RECT  2.304 28.283 3.51 28.949 ;
     RECT  2.304 28.949 2.697 28.985 ;
     RECT  3.492 28.949 3.51 29.219 ;
     RECT  2.34 28.985 2.697 29.255 ;
     RECT  2.415 29.255 2.697 29.987 ;
     RECT  5.115 28.409 5.397 29.987 ;
     RECT  7.815 28.823 8.097 29.987 ;
     RECT  10.515 28.409 10.797 29.987 ;
     RECT  13.215 27.917 13.497 29.987 ;
     RECT  15.915 26.909 16.197 29.987 ;
     RECT  18.615 27.773 18.897 29.987 ;
     RECT  2.415 29.987 2.505 30.257 ;
     RECT  5.115 29.987 5.205 30.257 ;
     RECT  7.815 29.987 7.905 30.257 ;
     RECT  10.515 29.987 10.605 30.257 ;
     RECT  13.215 29.987 13.305 30.257 ;
     RECT  15.915 29.987 16.005 30.257 ;
     RECT  18.615 29.987 18.705 30.257 ;
    LAYER M4 ;
     RECT  0.192 4.32 0.205 4.344 ;
     RECT  0.156 4.344 0.205 4.512 ;
     RECT  0.192 4.512 0.205 4.536 ;
     RECT  0.156 4.536 0.205 4.704 ;
     RECT  0.192 4.704 0.205 4.728 ;
     RECT  0.156 4.728 0.205 4.848 ;
     RECT  0.192 4.848 0.205 4.872 ;
     RECT  0.156 4.872 0.205 5.04 ;
     RECT  0.192 5.04 0.205 5.064 ;
     RECT  0.156 5.064 0.205 5.184 ;
     RECT  0.192 5.184 0.205 5.208 ;
     RECT  0.156 5.208 0.205 5.376 ;
     RECT  0.192 5.376 0.205 5.4 ;
     RECT  0.156 5.4 0.205 5.568 ;
     RECT  0.192 5.568 0.205 5.592 ;
     RECT  0.156 5.592 0.205 5.712 ;
     RECT  0.192 5.712 0.205 5.736 ;
     RECT  0.156 5.736 0.205 5.904 ;
     RECT  0.192 5.904 0.205 5.928 ;
     RECT  0.156 5.928 0.205 6.096 ;
     RECT  0.192 6.096 0.205 6.12 ;
     RECT  0.156 6.12 0.205 6.24 ;
     RECT  0.192 6.24 0.205 6.264 ;
     RECT  0.156 6.264 0.205 6.432 ;
     RECT  0.192 6.432 0.205 6.456 ;
     RECT  0.156 6.456 0.205 6.624 ;
     RECT  0.192 6.624 0.205 6.648 ;
     RECT  0.156 6.648 0.205 6.768 ;
     RECT  0.192 6.768 0.205 6.792 ;
     RECT  0.156 6.792 0.205 6.96 ;
     RECT  0.192 6.96 0.205 6.984 ;
     RECT  0.156 6.984 0.205 7.104 ;
     RECT  0.192 7.104 0.205 7.128 ;
     RECT  0.156 7.128 0.205 7.296 ;
     RECT  0.192 7.296 0.205 7.32 ;
     RECT  0.156 7.32 0.205 7.488 ;
     RECT  0.192 7.488 0.205 7.512 ;
     RECT  0.156 7.512 0.205 7.632 ;
     RECT  0.192 7.632 0.205 7.656 ;
     RECT  0.156 7.656 0.205 7.824 ;
     RECT  0.192 7.824 0.205 7.848 ;
     RECT  0.156 7.848 0.205 8.016 ;
     RECT  0.192 8.016 0.205 8.04 ;
     RECT  0.156 8.04 0.205 8.16 ;
     RECT  0.192 8.16 0.205 8.184 ;
     RECT  0.156 8.184 0.205 8.352 ;
     RECT  0.192 8.352 0.205 8.376 ;
     RECT  0.156 8.376 0.205 8.544 ;
     RECT  0.192 8.544 0.205 8.568 ;
     RECT  0.156 8.568 0.205 8.688 ;
     RECT  0.192 8.688 0.205 8.712 ;
     RECT  0.156 8.712 0.205 8.88 ;
     RECT  0.192 8.88 0.205 8.904 ;
     RECT  0.156 8.904 0.205 9.072 ;
     RECT  0.192 9.072 0.205 9.096 ;
     RECT  0.156 9.096 0.205 9.216 ;
     RECT  0.192 9.216 0.205 9.24 ;
     RECT  0.156 9.24 0.205 9.408 ;
     RECT  0.192 9.408 0.205 9.432 ;
     RECT  0.156 9.432 0.205 9.552 ;
     RECT  0.192 9.552 0.205 9.576 ;
     RECT  0.156 9.576 0.205 9.744 ;
     RECT  0.192 9.744 0.205 9.768 ;
     RECT  0.156 9.768 0.205 9.936 ;
     RECT  0.192 9.936 0.205 9.96 ;
     RECT  0.156 9.96 0.205 10.08 ;
     RECT  0.192 10.08 0.205 10.104 ;
     RECT  0.156 10.104 0.205 10.272 ;
     RECT  0.192 10.272 0.205 10.296 ;
     RECT  0.156 10.296 0.205 10.464 ;
     RECT  0.192 10.464 0.205 10.488 ;
     RECT  0.156 10.488 0.205 10.608 ;
     RECT  0.192 10.608 0.205 10.632 ;
     RECT  0.156 10.632 0.205 10.8 ;
     RECT  0.192 10.8 0.205 10.824 ;
     RECT  0.156 10.824 0.205 10.992 ;
     RECT  0.192 10.992 0.205 11.016 ;
     RECT  0.156 11.016 0.205 11.136 ;
     RECT  0.192 11.136 0.205 11.16 ;
     RECT  0.156 11.16 0.205 11.328 ;
     RECT  0.192 11.328 0.205 11.352 ;
     RECT  0.156 11.352 0.205 11.472 ;
     RECT  0.192 11.472 0.205 11.496 ;
     RECT  0.156 11.496 0.205 11.664 ;
     RECT  0.192 11.664 0.205 11.688 ;
     RECT  0.156 11.688 0.205 11.856 ;
     RECT  0.192 11.856 0.205 11.88 ;
     RECT  0.156 11.88 0.205 12 ;
     RECT  0.192 12 0.205 12.024 ;
     RECT  0.156 12.024 0.205 12.192 ;
     RECT  0.192 12.192 0.205 12.216 ;
     RECT  0.156 12.216 0.205 12.384 ;
     RECT  0.192 12.384 0.205 12.408 ;
     RECT  0.156 12.408 0.205 12.528 ;
     RECT  0.192 12.528 0.205 12.552 ;
     RECT  0.156 12.552 0.205 12.72 ;
     RECT  0.192 12.72 0.205 12.744 ;
     RECT  0.156 12.744 0.205 12.912 ;
     RECT  0.192 12.912 0.205 12.936 ;
     RECT  0.156 12.936 0.205 13.056 ;
     RECT  0.192 13.056 0.205 13.08 ;
     RECT  0.156 13.08 0.205 13.248 ;
     RECT  0.192 13.248 0.205 13.272 ;
     RECT  0.156 13.272 0.205 13.44 ;
     RECT  0.192 13.44 0.205 13.464 ;
     RECT  0.156 13.464 0.205 13.584 ;
     RECT  0.192 13.584 0.205 13.608 ;
     RECT  0.156 13.608 0.205 13.776 ;
     RECT  0.192 13.776 0.205 13.8 ;
     RECT  0.156 13.8 0.205 13.92 ;
     RECT  0.192 13.92 0.205 13.944 ;
     RECT  0.156 13.944 0.205 14.112 ;
     RECT  0.192 14.112 0.205 14.136 ;
     RECT  0.156 14.136 0.205 14.304 ;
     RECT  0.192 14.304 0.205 14.328 ;
     RECT  0.156 14.328 0.205 14.448 ;
     RECT  0.192 14.448 0.205 14.472 ;
     RECT  0.156 14.472 0.205 14.64 ;
     RECT  0.192 14.64 0.205 14.664 ;
     RECT  0.156 14.664 0.205 14.832 ;
     RECT  0.192 14.832 0.205 14.856 ;
     RECT  0.156 14.856 0.205 14.976 ;
     RECT  0.192 14.976 0.205 15 ;
     RECT  0.156 15 0.205 15.168 ;
     RECT  0.192 15.168 0.205 15.192 ;
     RECT  0.156 15.192 0.205 15.36 ;
     RECT  0.192 15.36 0.205 15.384 ;
     RECT  0.156 15.384 0.205 15.504 ;
     RECT  0.192 15.504 0.205 15.528 ;
     RECT  0.156 15.528 0.205 15.696 ;
     RECT  0.192 15.696 0.205 15.72 ;
     RECT  0.156 15.72 0.205 15.84 ;
     RECT  0.192 15.84 0.205 15.864 ;
     RECT  0.156 15.864 0.205 16.032 ;
     RECT  0.192 16.032 0.205 16.056 ;
     RECT  0.156 16.056 0.205 16.224 ;
     RECT  0.192 16.224 0.205 16.248 ;
     RECT  0.156 16.248 0.205 16.368 ;
     RECT  0.192 16.368 0.205 16.392 ;
     RECT  0.156 16.392 0.205 16.56 ;
     RECT  0.192 16.56 0.205 16.584 ;
     RECT  0.156 16.584 0.205 16.752 ;
     RECT  0.192 16.752 0.205 16.776 ;
     RECT  0.156 16.776 0.205 16.896 ;
     RECT  0.192 16.896 0.205 16.92 ;
     RECT  0.156 16.92 0.205 17.088 ;
     RECT  0.192 17.088 0.205 17.112 ;
     RECT  0.156 17.112 0.205 17.28 ;
     RECT  0.192 17.28 0.205 17.304 ;
     RECT  0.156 17.304 0.205 17.424 ;
     RECT  0.192 17.424 0.205 17.448 ;
     RECT  0.156 17.448 0.205 17.616 ;
     RECT  0.192 17.616 0.205 17.64 ;
     RECT  0.156 17.64 0.205 17.808 ;
     RECT  0.192 17.808 0.205 17.832 ;
     RECT  0.156 17.832 0.205 17.952 ;
     RECT  0.192 17.952 0.205 17.976 ;
     RECT  0.156 17.976 0.205 18.144 ;
     RECT  0.192 18.144 0.205 18.168 ;
     RECT  0.156 18.168 0.205 18.288 ;
     RECT  0.192 18.288 0.205 18.312 ;
     RECT  0.156 18.312 0.205 18.48 ;
     RECT  0.192 18.48 0.205 18.504 ;
     RECT  0.156 18.504 0.205 18.672 ;
     RECT  0.192 18.672 0.205 18.696 ;
     RECT  0.156 18.696 0.205 18.816 ;
     RECT  0.192 18.816 0.205 18.84 ;
     RECT  0.156 18.84 0.205 19.008 ;
     RECT  0.192 19.008 0.205 19.032 ;
     RECT  0.156 19.032 0.205 19.2 ;
     RECT  0.192 19.2 0.205 19.224 ;
     RECT  0.156 19.224 0.205 19.344 ;
     RECT  0.192 19.344 0.205 19.368 ;
     RECT  0.156 19.368 0.205 19.536 ;
     RECT  0.192 19.536 0.205 19.56 ;
     RECT  0.156 19.56 0.205 19.728 ;
     RECT  0.192 19.728 0.205 19.752 ;
     RECT  0.156 19.752 0.205 19.872 ;
     RECT  0.192 19.872 0.205 19.896 ;
     RECT  0.156 19.896 0.205 20.064 ;
     RECT  0.192 20.064 0.205 20.088 ;
     RECT  0.156 20.088 0.205 20.208 ;
     RECT  0.192 20.208 0.205 20.232 ;
     RECT  0.156 20.232 0.205 20.4 ;
     RECT  0.192 20.4 0.205 20.424 ;
     RECT  0.156 20.424 0.205 20.592 ;
     RECT  0.192 20.592 0.205 20.616 ;
     RECT  0.156 20.616 0.205 20.736 ;
     RECT  0.192 20.736 0.205 20.76 ;
     RECT  0.156 20.76 0.205 20.928 ;
     RECT  0.192 20.928 0.205 20.952 ;
     RECT  0.156 20.952 0.205 21.12 ;
     RECT  0.192 21.12 0.205 21.144 ;
     RECT  0.156 21.144 0.205 21.264 ;
     RECT  0.192 21.264 0.205 21.288 ;
     RECT  0.156 21.288 0.205 21.456 ;
     RECT  0.192 21.456 0.205 21.48 ;
     RECT  0.156 21.48 0.205 21.648 ;
     RECT  0.192 21.648 0.205 21.672 ;
     RECT  0.156 21.672 0.205 21.792 ;
     RECT  0.192 21.792 0.205 21.816 ;
     RECT  0.156 21.816 0.205 21.984 ;
     RECT  0.192 21.984 0.205 22.008 ;
     RECT  0.156 22.008 0.205 22.128 ;
     RECT  0.192 22.128 0.205 22.152 ;
     RECT  0.156 22.152 0.205 22.32 ;
     RECT  0.192 22.32 0.205 22.344 ;
     RECT  0.156 22.344 0.205 22.512 ;
     RECT  0.192 22.512 0.205 22.536 ;
     RECT  0.156 22.536 0.205 22.656 ;
     RECT  0.192 22.656 0.205 22.68 ;
     RECT  0.156 22.68 0.205 22.848 ;
     RECT  0.192 22.848 0.205 22.872 ;
     RECT  0.156 22.872 0.205 23.04 ;
     RECT  0.192 23.04 0.205 23.064 ;
     RECT  0.156 23.064 0.205 23.184 ;
     RECT  0.192 23.184 0.205 23.208 ;
     RECT  0.156 23.208 0.205 23.376 ;
     RECT  0.192 23.376 0.205 23.4 ;
     RECT  0.156 23.4 0.205 23.568 ;
     RECT  0.192 23.568 0.205 23.592 ;
     RECT  0.156 23.592 0.205 23.712 ;
     RECT  0.192 23.712 0.205 23.736 ;
     RECT  0.156 23.736 0.205 23.904 ;
     RECT  0.192 23.904 0.205 23.928 ;
     RECT  0.156 23.928 0.205 24.096 ;
     RECT  0.192 24.096 0.205 24.12 ;
     RECT  0.156 24.12 0.205 24.24 ;
     RECT  0.192 24.24 0.205 24.264 ;
     RECT  0.156 24.264 0.205 24.432 ;
     RECT  0.192 24.432 0.205 24.456 ;
     RECT  0.156 24.456 0.205 24.576 ;
     RECT  0.192 24.576 0.205 24.6 ;
     RECT  0.156 24.6 0.205 24.768 ;
     RECT  0.192 24.768 0.205 24.792 ;
     RECT  0.156 24.792 0.205 24.96 ;
     RECT  0.192 24.96 0.205 24.984 ;
     RECT  0.156 24.984 0.205 25.104 ;
     RECT  0.192 25.104 0.205 25.128 ;
     RECT  0.156 25.128 0.205 25.296 ;
     RECT  0.192 25.296 0.205 25.32 ;
     RECT  0.156 25.32 0.205 25.488 ;
     RECT  0.192 25.488 0.205 25.512 ;
     RECT  0.156 25.512 0.205 25.632 ;
     RECT  0.192 25.632 0.205 25.656 ;
     RECT  0.156 25.656 0.205 25.824 ;
     RECT  0.192 25.824 0.205 25.848 ;
     RECT  0.156 25.848 0.205 26.016 ;
     RECT  0.192 26.016 0.205 26.04 ;
     RECT  0.156 26.04 0.205 26.16 ;
     RECT  0.192 26.16 0.205 26.184 ;
     RECT  0.156 26.184 0.205 26.352 ;
     RECT  0.192 26.352 0.205 26.376 ;
     RECT  0.156 26.376 0.205 26.496 ;
     RECT  0.192 26.496 0.205 26.52 ;
     RECT  0.156 26.52 0.205 26.688 ;
     RECT  0.192 26.688 0.205 26.712 ;
     RECT  0.156 26.712 0.205 26.88 ;
     RECT  0.192 26.88 0.205 26.904 ;
     RECT  0.156 26.904 0.205 27.024 ;
     RECT  0.192 27.024 0.205 27.048 ;
     RECT  0.156 27.048 0.205 27.216 ;
     RECT  0.192 27.216 0.205 27.24 ;
     RECT  0.156 27.24 0.205 27.408 ;
     RECT  0.192 27.408 0.205 27.432 ;
     RECT  0.156 27.432 0.205 27.552 ;
     RECT  0.192 27.552 0.205 27.576 ;
     RECT  0.156 27.576 0.205 27.744 ;
     RECT  0.192 27.744 0.205 27.768 ;
     RECT  0.156 27.768 0.205 27.936 ;
     RECT  0.192 27.936 0.205 27.96 ;
     RECT  0.156 27.96 0.205 28.08 ;
     RECT  0.192 28.08 0.205 28.104 ;
     RECT  0.205 4.32 0.245 28.248 ;
     RECT  0.245 4.512 2.408 28.248 ;
     RECT  2.408 2.148 2.512 30.252 ;
     RECT  2.512 2.418 2.704 29.982 ;
     RECT  2.704 4.704 2.765 4.728 ;
     RECT  2.704 24.432 2.765 24.984 ;
     RECT  2.704 5.712 2.837 9 ;
     RECT  2.704 10.08 2.873 12.552 ;
     RECT  2.704 18.144 2.873 18.168 ;
     RECT  2.704 19.92 2.945 20.616 ;
     RECT  2.704 13.536 3.017 16.248 ;
     RECT  2.873 11.04 3.089 12.552 ;
     RECT  3.017 15.408 3.161 16.248 ;
     RECT  2.837 5.712 3.341 5.736 ;
     RECT  2.765 24.96 3.377 24.984 ;
     RECT  3.089 11.04 3.485 11.16 ;
     RECT  3.017 13.536 3.485 14.424 ;
     RECT  2.837 7.632 3.521 9 ;
     RECT  2.704 23.328 3.697 23.352 ;
     RECT  2.704 21.648 3.949 21.672 ;
     RECT  3.485 11.04 4.025 11.064 ;
     RECT  3.089 12.528 4.129 12.552 ;
     RECT  4.093 27.216 4.165 27.24 ;
     RECT  3.949 21.552 4.201 21.672 ;
     RECT  3.697 22.752 4.201 23.352 ;
     RECT  3.521 7.632 4.237 7.656 ;
     RECT  4.201 21.552 4.237 23.352 ;
     RECT  3.161 16.224 4.261 16.248 ;
     RECT  4.22 17.424 4.261 17.448 ;
     RECT  4.22 18.672 4.261 18.696 ;
     RECT  4.237 21.072 4.417 23.352 ;
     RECT  4.129 12.24 4.549 12.552 ;
     RECT  3.485 13.584 4.549 14.424 ;
     RECT  4.261 16.224 4.549 18.696 ;
     RECT  4.549 15.744 4.597 18.696 ;
     RECT  2.945 19.92 4.597 19.944 ;
     RECT  3.521 8.976 4.633 9 ;
     RECT  4.633 8.784 4.693 9 ;
     RECT  4.237 7.392 4.789 7.656 ;
     RECT  4.789 6.864 4.813 7.656 ;
     RECT  4.693 8.784 4.813 9.096 ;
     RECT  4.165 26.784 4.813 27.24 ;
     RECT  4.813 26.784 4.849 27.96 ;
     RECT  4.813 6.864 5.108 9.096 ;
     RECT  4.237 10.224 5.108 10.248 ;
     RECT  4.597 11.232 5.108 11.256 ;
     RECT  4.549 12.24 5.108 14.424 ;
     RECT  4.597 15.744 5.108 19.944 ;
     RECT  4.417 20.976 5.108 23.352 ;
     RECT  4.237 25.68 5.108 25.704 ;
     RECT  4.849 26.736 5.108 27.96 ;
     RECT  5.108 2.148 5.212 30.252 ;
     RECT  5.212 2.418 5.404 29.982 ;
     RECT  5.404 12.24 5.573 13.608 ;
     RECT  5.404 20.976 5.573 21.192 ;
     RECT  5.404 10.848 5.717 11.256 ;
     RECT  5.404 22.32 5.897 22.344 ;
     RECT  5.404 8.496 6.035 9.624 ;
     RECT  5.717 11.136 6.077 11.256 ;
     RECT  6.035 8.784 6.113 9.624 ;
     RECT  5.404 16.128 6.275 16.248 ;
     RECT  5.404 19.584 6.275 19.608 ;
     RECT  5.573 21.168 6.275 21.192 ;
     RECT  6.113 8.784 6.329 9.096 ;
     RECT  5.404 26.736 6.467 26.76 ;
     RECT  6.38 27.84 6.467 28.776 ;
     RECT  5.404 17.76 6.545 18.216 ;
     RECT  5.573 13.056 6.725 13.608 ;
     RECT  5.404 24.768 6.725 24.792 ;
     RECT  6.397 22.176 6.793 22.2 ;
     RECT  5.404 23.328 6.805 23.352 ;
     RECT  6.275 16.224 6.829 16.248 ;
     RECT  6.793 21.648 6.973 22.2 ;
     RECT  6.805 23.328 6.973 23.976 ;
     RECT  7.729 7.968 7.808 7.992 ;
     RECT  6.329 9.072 7.808 9.096 ;
     RECT  6.725 13.056 7.808 13.08 ;
     RECT  7.441 15.024 7.808 15.048 ;
     RECT  6.829 16.224 7.808 16.344 ;
     RECT  6.545 18.192 7.808 18.216 ;
     RECT  6.973 21.648 7.808 23.976 ;
     RECT  7.081 26.784 7.808 26.808 ;
     RECT  7.808 2.148 7.912 30.252 ;
     RECT  7.912 2.418 8.104 29.982 ;
     RECT  8.104 7.968 8.165 7.992 ;
     RECT  8.104 10.08 8.165 10.104 ;
     RECT  8.104 23.04 8.165 23.064 ;
     RECT  8.104 26.784 8.201 27.72 ;
     RECT  8.104 6.096 8.243 6.12 ;
     RECT  8.104 4.464 8.245 4.488 ;
     RECT  8.201 26.88 8.309 27.72 ;
     RECT  8.104 18.192 8.849 18.216 ;
     RECT  8.104 15.024 9.029 15.096 ;
     RECT  8.309 27.696 9.133 27.72 ;
     RECT  9.133 27.696 9.209 27.912 ;
     RECT  9.029 15.024 9.353 15.048 ;
     RECT  8.104 22.032 9.353 22.056 ;
     RECT  10.429 1.728 10.508 1.752 ;
     RECT  10.213 5.184 10.508 5.208 ;
     RECT  8.104 16.32 10.508 16.344 ;
     RECT  9.209 27.888 10.508 27.912 ;
     RECT  10.508 1.728 10.612 30.252 ;
     RECT  10.612 1.728 10.804 29.982 ;
     RECT  10.804 1.728 10.835 1.752 ;
     RECT  10.804 27.888 12.049 27.96 ;
     RECT  10.804 16.272 12.193 16.584 ;
     RECT  10.804 5.184 13.208 5.208 ;
     RECT  12.697 9.072 13.208 9.096 ;
     RECT  12.805 12.528 13.208 12.552 ;
     RECT  12.193 15.312 13.208 16.584 ;
     RECT  10.804 23.568 13.208 23.592 ;
     RECT  10.804 25.488 13.208 25.512 ;
     RECT  12.049 27.408 13.208 27.96 ;
     RECT  13.208 2.148 13.312 30.252 ;
     RECT  13.312 2.418 13.504 29.982 ;
     RECT  13.504 25.488 14.713 25.512 ;
     RECT  13.504 8.688 14.861 9.096 ;
     RECT  14.713 25.488 14.861 25.608 ;
     RECT  13.504 27.408 15.217 27.96 ;
     RECT  13.504 5.184 15.908 5.208 ;
     RECT  14.861 8.784 15.908 9.096 ;
     RECT  13.504 12.528 15.908 12.552 ;
     RECT  15.181 13.68 15.908 13.704 ;
     RECT  13.504 15.312 15.908 16.584 ;
     RECT  14.965 17.664 15.908 17.688 ;
     RECT  13.504 22.32 15.908 23.592 ;
     RECT  14.861 25.488 15.908 25.512 ;
     RECT  15.217 26.88 15.908 27.96 ;
     RECT  15.908 2.148 16.012 30.252 ;
     RECT  16.012 2.418 16.204 29.982 ;
     RECT  16.204 5.184 18.608 5.208 ;
     RECT  16.204 8.784 18.608 9.096 ;
     RECT  16.204 12.528 18.608 12.552 ;
     RECT  16.204 13.68 18.608 13.704 ;
     RECT  16.204 15.312 18.608 16.584 ;
     RECT  16.204 17.664 18.608 17.688 ;
     RECT  16.204 22.32 18.608 23.592 ;
     RECT  16.204 25.488 18.608 25.512 ;
     RECT  16.204 26.88 18.608 27.96 ;
     RECT  18.608 2.148 18.712 30.252 ;
     RECT  18.712 2.418 18.904 29.982 ;
     RECT  18.904 5.184 19.933 5.208 ;
     RECT  18.904 7.824 19.933 9.096 ;
     RECT  18.904 10.272 19.933 10.296 ;
     RECT  18.904 12 19.933 18.696 ;
     RECT  18.904 20.592 19.933 20.616 ;
     RECT  18.904 22.32 19.933 23.592 ;
     RECT  19.933 5.04 20.473 5.208 ;
     RECT  19.933 20.592 20.473 23.592 ;
     RECT  18.904 24.768 20.473 25.656 ;
     RECT  20.473 5.04 20.509 5.928 ;
     RECT  19.933 7.104 20.509 9.096 ;
     RECT  19.933 10.272 20.509 18.84 ;
     RECT  20.473 19.872 20.509 25.656 ;
     RECT  18.904 26.88 20.509 27.96 ;
     RECT  20.509 4.32 21.408 4.344 ;
     RECT  20.509 4.344 21.42 4.512 ;
     RECT  20.509 4.512 21.408 4.536 ;
     RECT  20.509 4.536 21.42 4.704 ;
     RECT  20.509 4.704 21.408 4.728 ;
     RECT  20.509 4.728 21.42 4.848 ;
     RECT  20.509 4.848 21.408 4.872 ;
     RECT  20.509 4.872 21.42 5.04 ;
     RECT  20.509 5.04 21.408 5.064 ;
     RECT  20.509 5.064 21.42 5.184 ;
     RECT  20.509 5.184 21.408 5.208 ;
     RECT  20.509 5.208 21.42 5.376 ;
     RECT  20.509 5.376 21.408 5.4 ;
     RECT  20.509 5.4 21.42 5.568 ;
     RECT  20.509 5.568 21.408 5.592 ;
     RECT  20.509 5.592 21.42 5.712 ;
     RECT  20.509 5.712 21.408 5.736 ;
     RECT  20.509 5.736 21.42 5.904 ;
     RECT  20.509 5.904 21.408 5.928 ;
     RECT  20.509 5.928 21.42 6.096 ;
     RECT  20.509 6.096 21.408 6.12 ;
     RECT  20.509 6.12 21.42 6.24 ;
     RECT  20.509 6.24 21.408 6.264 ;
     RECT  20.509 6.264 21.42 6.432 ;
     RECT  20.509 6.432 21.408 6.456 ;
     RECT  20.509 6.456 21.42 6.624 ;
     RECT  20.509 6.624 21.408 6.648 ;
     RECT  20.509 6.648 21.42 6.768 ;
     RECT  20.509 6.768 21.408 6.792 ;
     RECT  20.509 6.792 21.42 6.96 ;
     RECT  20.509 6.96 21.408 6.984 ;
     RECT  20.509 6.984 21.42 7.104 ;
     RECT  20.509 7.104 21.408 7.128 ;
     RECT  20.509 7.128 21.42 7.296 ;
     RECT  20.509 7.296 21.408 7.32 ;
     RECT  20.509 7.32 21.42 7.488 ;
     RECT  20.509 7.488 21.408 7.512 ;
     RECT  20.509 7.512 21.42 7.632 ;
     RECT  20.509 7.632 21.408 7.656 ;
     RECT  20.509 7.656 21.42 7.824 ;
     RECT  20.509 7.824 21.408 7.848 ;
     RECT  20.509 7.848 21.42 8.016 ;
     RECT  20.509 8.016 21.408 8.04 ;
     RECT  20.509 8.04 21.42 8.16 ;
     RECT  20.509 8.16 21.408 8.184 ;
     RECT  20.509 8.184 21.42 8.352 ;
     RECT  20.509 8.352 21.408 8.376 ;
     RECT  20.509 8.376 21.42 8.544 ;
     RECT  20.509 8.544 21.408 8.568 ;
     RECT  20.509 8.568 21.42 8.688 ;
     RECT  20.509 8.688 21.408 8.712 ;
     RECT  20.509 8.712 21.42 8.88 ;
     RECT  20.509 8.88 21.408 8.904 ;
     RECT  20.509 8.904 21.42 9.072 ;
     RECT  20.509 9.072 21.408 9.096 ;
     RECT  20.509 9.096 21.42 9.216 ;
     RECT  20.509 9.216 21.408 9.24 ;
     RECT  20.509 9.24 21.42 9.408 ;
     RECT  20.509 9.408 21.408 9.432 ;
     RECT  20.509 9.432 21.42 9.552 ;
     RECT  20.509 9.552 21.408 9.576 ;
     RECT  20.509 9.576 21.42 9.744 ;
     RECT  20.509 9.744 21.408 9.768 ;
     RECT  20.509 9.768 21.42 9.936 ;
     RECT  20.509 9.936 21.408 9.96 ;
     RECT  20.509 9.96 21.42 10.08 ;
     RECT  20.509 10.08 21.408 10.104 ;
     RECT  20.509 10.104 21.42 10.272 ;
     RECT  20.509 10.272 21.408 10.296 ;
     RECT  20.509 10.296 21.42 10.464 ;
     RECT  20.509 10.464 21.408 10.488 ;
     RECT  20.509 10.488 21.42 10.608 ;
     RECT  20.509 10.608 21.408 10.632 ;
     RECT  20.509 10.632 21.42 10.8 ;
     RECT  20.509 10.8 21.408 10.824 ;
     RECT  20.509 10.824 21.42 10.992 ;
     RECT  20.509 10.992 21.408 11.016 ;
     RECT  20.509 11.016 21.42 11.136 ;
     RECT  20.509 11.136 21.408 11.16 ;
     RECT  20.509 11.16 21.42 11.328 ;
     RECT  20.509 11.328 21.408 11.352 ;
     RECT  20.509 11.352 21.42 11.472 ;
     RECT  20.509 11.472 21.408 11.496 ;
     RECT  20.509 11.496 21.42 11.664 ;
     RECT  20.509 11.664 21.408 11.688 ;
     RECT  20.509 11.688 21.42 11.856 ;
     RECT  20.509 11.856 21.408 11.88 ;
     RECT  20.509 11.88 21.42 12 ;
     RECT  20.509 12 21.408 12.024 ;
     RECT  20.509 12.024 21.42 12.192 ;
     RECT  20.509 12.192 21.408 12.216 ;
     RECT  20.509 12.216 21.42 12.384 ;
     RECT  20.509 12.384 21.408 12.408 ;
     RECT  20.509 12.408 21.42 12.528 ;
     RECT  20.509 12.528 21.408 12.552 ;
     RECT  20.509 12.552 21.42 12.72 ;
     RECT  20.509 12.72 21.408 12.744 ;
     RECT  20.509 12.744 21.42 12.912 ;
     RECT  20.509 12.912 21.408 12.936 ;
     RECT  20.509 12.936 21.42 13.056 ;
     RECT  20.509 13.056 21.408 13.08 ;
     RECT  20.509 13.08 21.42 13.248 ;
     RECT  20.509 13.248 21.408 13.272 ;
     RECT  20.509 13.272 21.42 13.44 ;
     RECT  20.509 13.44 21.408 13.464 ;
     RECT  20.509 13.464 21.42 13.584 ;
     RECT  20.509 13.584 21.408 13.608 ;
     RECT  20.509 13.608 21.42 13.776 ;
     RECT  20.509 13.776 21.408 13.8 ;
     RECT  20.509 13.8 21.42 13.92 ;
     RECT  20.509 13.92 21.408 13.944 ;
     RECT  20.509 13.944 21.42 14.112 ;
     RECT  20.509 14.112 21.408 14.136 ;
     RECT  20.509 14.136 21.42 14.304 ;
     RECT  20.509 14.304 21.408 14.328 ;
     RECT  20.509 14.328 21.42 14.448 ;
     RECT  20.509 14.448 21.408 14.472 ;
     RECT  20.509 14.472 21.42 14.64 ;
     RECT  20.509 14.64 21.408 14.664 ;
     RECT  20.509 14.664 21.42 14.832 ;
     RECT  20.509 14.832 21.408 14.856 ;
     RECT  20.509 14.856 21.42 14.976 ;
     RECT  20.509 14.976 21.408 15 ;
     RECT  20.509 15 21.42 15.168 ;
     RECT  20.509 15.168 21.408 15.192 ;
     RECT  20.509 15.192 21.42 15.36 ;
     RECT  20.509 15.36 21.408 15.384 ;
     RECT  20.509 15.384 21.42 15.504 ;
     RECT  20.509 15.504 21.408 15.528 ;
     RECT  20.509 15.528 21.42 15.696 ;
     RECT  20.509 15.696 21.408 15.72 ;
     RECT  20.509 15.72 21.42 15.84 ;
     RECT  20.509 15.84 21.408 15.864 ;
     RECT  20.509 15.864 21.42 16.032 ;
     RECT  20.509 16.032 21.408 16.056 ;
     RECT  20.509 16.056 21.42 16.224 ;
     RECT  20.509 16.224 21.408 16.248 ;
     RECT  20.509 16.248 21.42 16.368 ;
     RECT  20.509 16.368 21.408 16.392 ;
     RECT  20.509 16.392 21.42 16.56 ;
     RECT  20.509 16.56 21.408 16.584 ;
     RECT  20.509 16.584 21.42 16.752 ;
     RECT  20.509 16.752 21.408 16.776 ;
     RECT  20.509 16.776 21.42 16.896 ;
     RECT  20.509 16.896 21.408 16.92 ;
     RECT  20.509 16.92 21.42 17.088 ;
     RECT  20.509 17.088 21.408 17.112 ;
     RECT  20.509 17.112 21.42 17.28 ;
     RECT  20.509 17.28 21.408 17.304 ;
     RECT  20.509 17.304 21.42 17.424 ;
     RECT  20.509 17.424 21.408 17.448 ;
     RECT  20.509 17.448 21.42 17.616 ;
     RECT  20.509 17.616 21.408 17.64 ;
     RECT  20.509 17.64 21.42 17.808 ;
     RECT  20.509 17.808 21.408 17.832 ;
     RECT  20.509 17.832 21.42 17.952 ;
     RECT  20.509 17.952 21.408 17.976 ;
     RECT  20.509 17.976 21.42 18.144 ;
     RECT  20.509 18.144 21.408 18.168 ;
     RECT  20.509 18.168 21.42 18.288 ;
     RECT  20.509 18.288 21.408 18.312 ;
     RECT  20.509 18.312 21.42 18.48 ;
     RECT  20.509 18.48 21.408 18.504 ;
     RECT  20.509 18.504 21.42 18.672 ;
     RECT  20.509 18.672 21.408 18.696 ;
     RECT  20.509 18.696 21.42 18.816 ;
     RECT  20.509 18.816 21.408 18.84 ;
     RECT  20.509 18.84 21.42 19.008 ;
     RECT  20.509 19.008 21.408 19.032 ;
     RECT  20.509 19.032 21.42 19.2 ;
     RECT  20.509 19.2 21.408 19.224 ;
     RECT  20.509 19.224 21.42 19.344 ;
     RECT  20.509 19.344 21.408 19.368 ;
     RECT  20.509 19.368 21.42 19.536 ;
     RECT  20.509 19.536 21.408 19.56 ;
     RECT  20.509 19.56 21.42 19.728 ;
     RECT  20.509 19.728 21.408 19.752 ;
     RECT  20.509 19.752 21.42 19.872 ;
     RECT  20.509 19.872 21.408 19.896 ;
     RECT  20.509 19.896 21.42 20.064 ;
     RECT  20.509 20.064 21.408 20.088 ;
     RECT  20.509 20.088 21.42 20.208 ;
     RECT  20.509 20.208 21.408 20.232 ;
     RECT  20.509 20.232 21.42 20.4 ;
     RECT  20.509 20.4 21.408 20.424 ;
     RECT  20.509 20.424 21.42 20.592 ;
     RECT  20.509 20.592 21.408 20.616 ;
     RECT  20.509 20.616 21.42 20.736 ;
     RECT  20.509 20.736 21.408 20.76 ;
     RECT  20.509 20.76 21.42 20.928 ;
     RECT  20.509 20.928 21.408 20.952 ;
     RECT  20.509 20.952 21.42 21.12 ;
     RECT  20.509 21.12 21.408 21.144 ;
     RECT  20.509 21.144 21.42 21.264 ;
     RECT  20.509 21.264 21.408 21.288 ;
     RECT  20.509 21.288 21.42 21.456 ;
     RECT  20.509 21.456 21.408 21.48 ;
     RECT  20.509 21.48 21.42 21.648 ;
     RECT  20.509 21.648 21.408 21.672 ;
     RECT  20.509 21.672 21.42 21.792 ;
     RECT  20.509 21.792 21.408 21.816 ;
     RECT  20.509 21.816 21.42 21.984 ;
     RECT  20.509 21.984 21.408 22.008 ;
     RECT  20.509 22.008 21.42 22.128 ;
     RECT  20.509 22.128 21.408 22.152 ;
     RECT  20.509 22.152 21.42 22.32 ;
     RECT  20.509 22.32 21.408 22.344 ;
     RECT  20.509 22.344 21.42 22.512 ;
     RECT  20.509 22.512 21.408 22.536 ;
     RECT  20.509 22.536 21.42 22.656 ;
     RECT  20.509 22.656 21.408 22.68 ;
     RECT  20.509 22.68 21.42 22.848 ;
     RECT  20.509 22.848 21.408 22.872 ;
     RECT  20.509 22.872 21.42 23.04 ;
     RECT  20.509 23.04 21.408 23.064 ;
     RECT  20.509 23.064 21.42 23.184 ;
     RECT  20.509 23.184 21.408 23.208 ;
     RECT  20.509 23.208 21.42 23.376 ;
     RECT  20.509 23.376 21.408 23.4 ;
     RECT  20.509 23.4 21.42 23.568 ;
     RECT  20.509 23.568 21.408 23.592 ;
     RECT  20.509 23.592 21.42 23.712 ;
     RECT  20.509 23.712 21.408 23.736 ;
     RECT  20.509 23.736 21.42 23.904 ;
     RECT  20.509 23.904 21.408 23.928 ;
     RECT  20.509 23.928 21.42 24.096 ;
     RECT  20.509 24.096 21.408 24.12 ;
     RECT  20.509 24.12 21.42 24.24 ;
     RECT  20.509 24.24 21.408 24.264 ;
     RECT  20.509 24.264 21.42 24.432 ;
     RECT  20.509 24.432 21.408 24.456 ;
     RECT  20.509 24.456 21.42 24.576 ;
     RECT  20.509 24.576 21.408 24.6 ;
     RECT  20.509 24.6 21.42 24.768 ;
     RECT  20.509 24.768 21.408 24.792 ;
     RECT  20.509 24.792 21.42 24.96 ;
     RECT  20.509 24.96 21.408 24.984 ;
     RECT  20.509 24.984 21.42 25.104 ;
     RECT  20.509 25.104 21.408 25.128 ;
     RECT  20.509 25.128 21.42 25.296 ;
     RECT  20.509 25.296 21.408 25.32 ;
     RECT  20.509 25.32 21.42 25.488 ;
     RECT  20.509 25.488 21.408 25.512 ;
     RECT  20.509 25.512 21.42 25.632 ;
     RECT  20.509 25.632 21.408 25.656 ;
     RECT  20.509 25.656 21.42 25.824 ;
     RECT  20.509 25.824 21.408 25.848 ;
     RECT  20.509 25.848 21.42 26.016 ;
     RECT  20.509 26.016 21.408 26.04 ;
     RECT  20.509 26.04 21.42 26.16 ;
     RECT  20.509 26.16 21.408 26.184 ;
     RECT  20.509 26.184 21.42 26.352 ;
     RECT  20.509 26.352 21.408 26.376 ;
     RECT  20.509 26.376 21.42 26.496 ;
     RECT  20.509 26.496 21.408 26.52 ;
     RECT  20.509 26.52 21.42 26.688 ;
     RECT  20.509 26.688 21.408 26.712 ;
     RECT  20.509 26.712 21.42 26.88 ;
     RECT  20.509 26.88 21.408 26.904 ;
     RECT  20.509 26.904 21.42 27.024 ;
     RECT  20.509 27.024 21.408 27.048 ;
     RECT  20.509 27.048 21.42 27.216 ;
     RECT  20.509 27.216 21.408 27.24 ;
     RECT  20.509 27.24 21.42 27.408 ;
     RECT  20.509 27.408 21.408 27.432 ;
     RECT  20.509 27.432 21.42 27.552 ;
     RECT  20.509 27.552 21.408 27.576 ;
     RECT  20.509 27.576 21.42 27.744 ;
     RECT  20.509 27.744 21.408 27.768 ;
     RECT  20.509 27.768 21.42 27.936 ;
     RECT  20.509 27.936 21.408 27.96 ;
     RECT  20.509 27.96 21.42 28.08 ;
     RECT  20.509 28.08 21.408 28.104 ;
     RECT  21.42 16.272 21.485 16.296 ;
     RECT  21.42 17.76 21.485 17.784 ;
    LAYER M5 ;
     RECT  10.8 1.763 10.812 2.137 ;
     RECT  2.4 2.137 2.52 2.151 ;
     RECT  5.1 2.137 5.22 2.151 ;
     RECT  7.8 2.137 7.92 2.151 ;
     RECT  13.2 2.137 13.32 2.151 ;
     RECT  15.9 2.137 16.02 2.151 ;
     RECT  18.6 2.137 18.72 2.151 ;
     RECT  7.8 2.151 8.112 4.453 ;
     RECT  7.8 4.453 8.232 6.131 ;
     RECT  2.4 2.151 2.712 6.565 ;
     RECT  2.4 6.565 2.808 6.755 ;
     RECT  5.1 2.151 5.412 6.853 ;
     RECT  4.8 6.853 5.412 7.427 ;
     RECT  5.1 7.427 5.412 8.485 ;
     RECT  5.1 8.485 6.024 9.061 ;
     RECT  4.704 9.061 6.024 9.589 ;
     RECT  4.704 9.589 6.072 10.259 ;
     RECT  5.1 10.259 6.072 13.045 ;
     RECT  5.1 13.045 6.264 13.381 ;
     RECT  4.56 13.381 6.264 16.501 ;
     RECT  4.272 16.501 6.264 18.707 ;
     RECT  5.1 18.707 6.264 23.317 ;
     RECT  7.8 6.131 8.112 23.317 ;
     RECT  5.1 23.317 8.112 23.363 ;
     RECT  6.816 23.363 8.112 23.987 ;
     RECT  5.1 23.363 5.412 26.725 ;
     RECT  4.896 26.725 5.412 27.971 ;
     RECT  6.432 26.725 6.456 28.787 ;
     RECT  2.4 6.755 2.712 30.249 ;
     RECT  5.1 27.971 5.412 30.249 ;
     RECT  7.8 23.987 8.112 30.249 ;
     RECT  10.5 2.137 10.812 30.249 ;
     RECT  13.2 2.151 13.512 30.249 ;
     RECT  15.9 2.151 16.212 30.249 ;
     RECT  18.6 2.151 18.912 30.249 ;
     RECT  2.4 30.249 2.52 30.263 ;
     RECT  5.1 30.249 5.22 30.263 ;
     RECT  7.8 30.249 7.92 30.263 ;
     RECT  10.5 30.249 10.62 30.263 ;
     RECT  13.2 30.249 13.32 30.263 ;
     RECT  15.9 30.249 16.02 30.263 ;
     RECT  18.6 30.249 18.72 30.263 ;
     RECT  5.412 23.363 6.816 23.987 ;
     RECT  5.412 26.725 6.432 28.787 ;
     RECT  6.456 26.725 7.8 28.787 ;
  END
END hbfd_rly_136_WE_fc
END LIBRARY
